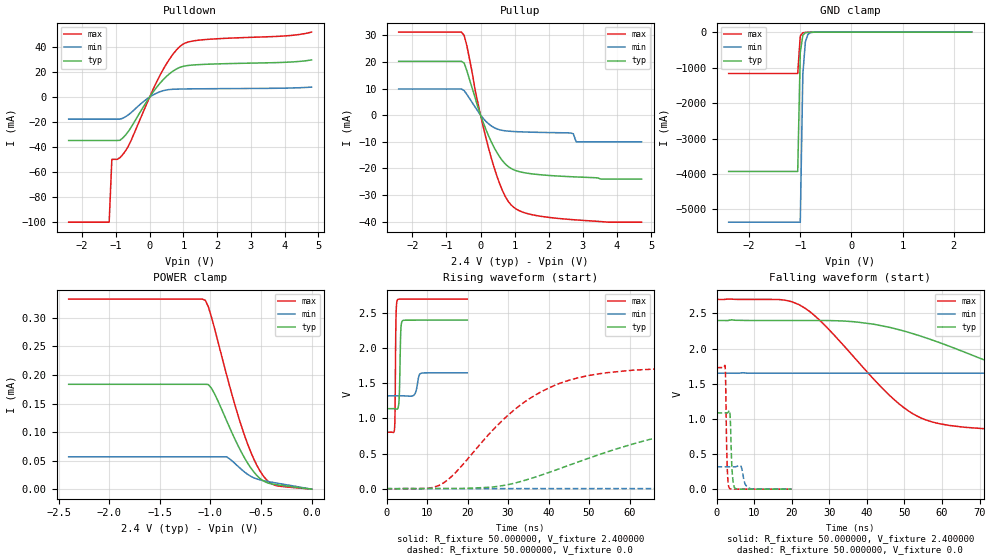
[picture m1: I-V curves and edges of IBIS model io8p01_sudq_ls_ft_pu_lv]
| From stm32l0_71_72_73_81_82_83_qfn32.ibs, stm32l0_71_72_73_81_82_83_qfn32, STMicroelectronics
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|   Model io8p01_sudq_ls_ft_pu_lv
[Model]  io8p01_sudq_ls_ft_pu_lv
Model_type I/O
Polarity   Non-Inverting
Enable   Active-Low
Vinl =   0.720000V
Vinh =   1.680000V
Vmeas =  1.200000V
Cref =   50.000000pF
Rref =   100.000000M
Vref =   0.0V
C_comp   2.317700pF   2.286600pF   2.332700pF
[Temperature Range]   25.000000   0.105000k   -40.000000
[Pullup Reference]   2.400000V   1.650000V   2.700000V
[Pulldown Reference]   0.0V   0.0V   0.0V
[POWER Clamp Reference]   2.400000V   1.650000V   2.700000V
[GND Clamp Reference]   0.0V   0.0V   0.0V
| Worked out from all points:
|   slope of the pulldown table from 0 to 0.36 V, typ, clamps not added: 28.4 ohm
|   slope of the pullup table from 0 to 0.36 V, typ, clamps not added: 32.2 ohm
|   GND clamp passes 1 mA (typ) near -0.65 V on its own axis
|   rising waveform, R_fixture 50.000000, V_fixture 2.400000: 20-80 % time 276ps typ, 630ps min, 183ps max; typ from 1.14 V to 2.4 V
|   rising waveform, R_fixture 50.000000, V_fixture 0.0: 20-80 % time 39.8ns typ, 107ns min, 19.4ns max; typ from 0.001 V to 1.09 V
|   falling waveform, R_fixture 50.000000, V_fixture 2.400000: 20-80 % time 41.3ns typ, 106ns min, 20.3ns max; typ from 2.4 V to 1.14 V
|   falling waveform, R_fixture 50.000000, V_fixture 0.0: 20-80 % time 457ps typ, 825ps min, 358ps max; typ from 1.09 V to 0.001 V
[Pulldown]
|Voltage   I(typ)   I(min)   I(max)
-2.4V     -34.71mA   -17.62mA   -100mA
-1.2V     -34.71mA   -17.62mA   -100mA
-1.12V    -34.71mA   -17.62mA   -49.77mA
-960mV    -34.71mA   -17.62mA   -49.77mA
-720mV    -30.52mA   -15.81mA   -43.24mA
-560mV    -24.66mA   -12.69mA   -35.31mA
-80mV     -3.3mA     -1.497mA   -4.982mA
320mV     11.47mA    4.39mA     18.08mA
640mV     19.72mA    6.139mA    32.34mA
960mV     24.33mA    6.432mA    41.77mA
1.52V     26.01mA    6.613mA    45.64mA
4.8V      29.64mA    7.944mA    51.92mA
[Pullup]
|Voltage   I(typ)   I(min)   I(max)
-2.4V     20.23mA    9.819mA    31.21mA
-560mV    20.23mA    9.819mA    31.21mA
-480mV    19.53mA    9.213mA    29.94mA
-400mV    16.65mA    7.776mA    25.99mA
0V        86fA       7.57pA     10fA
320mV     -10.16mA   -4.078mA   -16.34mA
640mV     -17.08mA   -5.718mA   -28.28mA
960mV     -20.45mA   -6.129mA   -34.49mA
2V        -22.64mA   -6.529mA   -38.4mA
2.72V     -23.16mA   -7mA       -39.27mA
2.8V      -23.2mA    -10mA      -39.35mA
4.72V     -24mA      -10mA      -40.2mA
[GND_clamp]
|Voltage   I(typ)   I(min)   I(max)
-2.4V     -3.929A    -5.359A    -1.166A
-1.05V    -3.929A    -5.359A    -1.166A
-1V       -574.5mA   -5.359A    -109.1mA
-950mV    -90.02mA   -1.192A    -18.55mA
-900mV    -18.41mA   -269.7mA   -9.049mA
-850mV    -6.764mA   -63.59mA   -6.579mA
-800mV    -4.027mA   -16.66mA   -4.859mA
-650mV    -1.043mA   -1.218mA   -1.146mA
2.35V     0A         0A         0A
[POWER_clamp]
|Voltage   I(typ)   I(min)   I(max)
-2.4V     183.7uA    56.67uA    333uA
-1.05V    183.7uA    56.67uA    330.8uA
-1.02V    183.2uA    56.67uA    319.3uA
-960mV    167.4uA    56.67uA    282.2uA
-840mV    120.1uA    56.67uA    200.3uA
-750mV    84.75uA    43.78uA    142.9uA
-690mV    63.55uA    34.11uA    108.5uA
-600mV    37.04uA    22.44uA    64.62uA
-510mV    18.73uA    16.34uA    31.91uA
-450mV    12.06uA    14.02uA    17.25uA
-360mV    8.154uA    11.11uA    6.782uA
0V        0A         0A         0A
[Ramp]
| variable   typ   min   max
dV/dt_r  0.65095/39.80921n   0.19020/0.10703u   1.03799/19.39127n
dV/dt_f  0.75624/41.29179n   0.19440/0.10610u   1.13751/20.24588n
R_load = 50.000000
[Rising Waveform]
R_fixture= 50.000000
V_fixture= 2.400000
V_fixture_min= 1.650000
V_fixture_max= 2.700000
|time   V(typ)   V(min)   V(max)
0s        1.14V      1.322V     804.2mV
1.962ns   1.14V      1.322V     842.5mV
2.122ns   1.138V     1.322V     1.188V
2.322ns   1.135V     1.322V     2.388V
2.683ns   1.134V     1.322V     2.687V
3.123ns   1.291V     1.323V     2.698V
3.524ns   2.247V     1.323V     2.699V
3.884ns   2.387V     1.323V     2.699V
8.569ns   2.4V       1.643V     2.7V
19.94ns   2.4V       1.65V      2.7V
[Rising Waveform]
R_fixture= 50.000000
V_fixture= 0.0
V_fixture_min= 0.0
V_fixture_max= 0.0
|time   V(typ)   V(min)   V(max)
0s        880.6uV    1.331mV    514.3uV
14.01ns   2.444mV    2.471mV    80.72mV
29.03ns   48.03mV    2.472mV    995mV
39.04ns   210.9mV    2.471mV    1.405V
48.05ns   396.2mV    2.479mV    1.589V
61.06ns   640.4mV    2.512mV    1.688V
85.09ns   917.7mV    3.566mV    1.725V
122.1ns   1.055V     40.2mV     1.73V
254.3ns   1.086V     268.1mV    1.73V
498.5ns   1.086V     318.6mV    1.73V
[Falling Waveform]
R_fixture= 50.000000
V_fixture= 2.400000
V_fixture_min= 1.650000
V_fixture_max= 2.700000
|time   V(typ)   V(min)   V(max)
0s        2.4V       1.65V      2.7V
22.02ns   2.4V       1.65V      2.624V
37.04ns   2.38V      1.65V      1.851V
52.05ns   2.216V     1.65V      1.079V
59.06ns   2.091V     1.65V      935.3mV
73.07ns   1.8V       1.65V      853.8mV
100.1ns   1.363V     1.65V      816mV
137.1ns   1.202V     1.636V     806mV
291.3ns   1.14V      1.38V      804.2mV
498.5ns   1.14V      1.322V     804.2mV
[Falling Waveform]
R_fixture= 50.000000
V_fixture= 0.0
V_fixture_min= 0.0
V_fixture_max= 0.0
|time   V(typ)   V(min)   V(max)
0s        1.086V     318.6mV    1.73V
2.282ns   1.086V     318.6mV    1.747V
2.402ns   1.086V     318.6mV    1.588V
2.843ns   1.085V     318.6mV    325.9mV
3.403ns   1.12V      318.6mV    16.81mV
3.644ns   1.017V     318.6mV    5.428mV
4.164ns   249.2mV    318.4mV    710.8uV
4.885ns   14.25mV    318.3mV    488.6uV
8.889ns   876.6uV    9.686mV    493.4uV
19.94ns   880.6uV    1.331mV    514.3uV
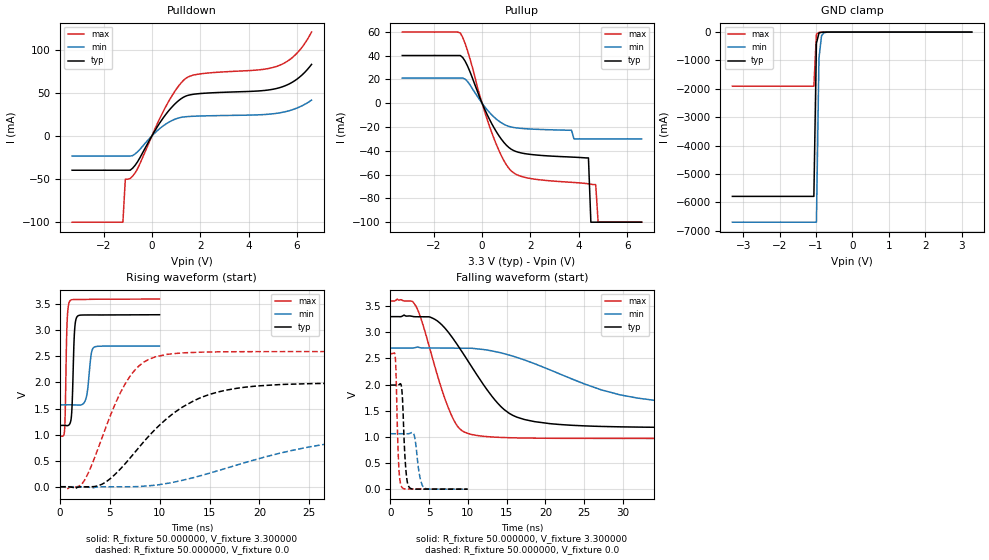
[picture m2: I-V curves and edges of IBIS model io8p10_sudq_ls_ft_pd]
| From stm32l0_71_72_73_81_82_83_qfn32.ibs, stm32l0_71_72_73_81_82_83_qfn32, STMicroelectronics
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|   Model io8p10_sudq_ls_ft_pd
[Model]  io8p10_sudq_ls_ft_pd
Model_type I/O
Polarity   Non-Inverting
Enable   Active-Low
Vinl =   0.990000V
Vinh =   2.310000V
Vmeas =  1.650000V
Cref =   50.000000pF
Rref =   100.000000M
Vref =   0.0V
C_comp   2.343000pF   2.309800pF   2.393900pF
[Temperature Range]   25.000000   0.125000k   -40.000000
[Pullup Reference]   3.300000V   2.700000V   3.600000V
[Pulldown Reference]   0.0V   0.0V   0.0V
[POWER Clamp Reference]   3.300000V   2.700000V   3.600000V
[GND Clamp Reference]   0.0V   0.0V   0.0V
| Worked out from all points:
|   slope of the pulldown table from 0 to 0.495 V, typ, clamps not added: 22.6 ohm
|   slope of the pullup table from 0 to 0.495 V, typ, clamps not added: 23.9 ohm
|   GND clamp passes 1 mA (typ) near -0.64 V on its own axis
|   rising waveform, R_fixture 50.000000, V_fixture 3.300000: 20-80 % time 207ps typ, 360ps min, 165ps max; typ from 1.18 V to 3.3 V
|   rising waveform, R_fixture 50.000000, V_fixture 0.0: 20-80 % time 6.56ns typ, 13.6ns min, 3.47ns max; typ from 0 V to 1.99 V
|   falling waveform, R_fixture 50.000000, V_fixture 3.300000: 20-80 % time 6.01ns typ, 12.6ns min, 3.3ns max; typ from 3.3 V to 1.18 V
|   falling waveform, R_fixture 50.000000, V_fixture 0.0: 20-80 % time 379ps typ, 552ps min, 301ps max; typ from 1.99 V to 0 V
[Pulldown]
|Voltage   I(typ)   I(min)   I(max)
-3.3V     -39.8mA    -23.38mA   -100mA
-1.2V     -39.8mA    -23.38mA   -100mA
-1.1V     -39.8mA    -23.38mA   -50.11mA
-900mV    -39.8mA    -23.38mA   -49.43mA
-700mV    -34.25mA   -21mA      -43.13mA
600mV     25.84mA    14.18mA    35.34mA
1V        38.32mA    19.82mA    53.81mA
1.4V      46.09mA    22.19mA    66.63mA
2V        49.05mA    23.02mA    71.83mA
5.2V      55.23mA    26.32mA    80.92mA
6V        65.76mA    32.26mA    95.84mA
6.6V      82.81mA    41.44mA    120.2mA
[Pullup]
|Voltage   I(typ)   I(min)   I(max)
-3.3V     40.02mA    21.08mA    59.7mA
-900mV    40.02mA    21.08mA    58.93mA
-600mV    31.19mA    18.17mA    44.04mA
500mV     -20.88mA   -11.78mA   -30.07mA
1.3V      -39.75mA   -20.41mA   -58.47mA
3.7V      -45.29mA   -22.8mA    -66.51mA
3.8V      -45.39mA   -30mA      -66.64mA
4.4V      -46mA      -30mA      -67.77mA
4.5V      -100mA     -30mA      -68.06mA
4.7V      -100mA     -30mA      -68.41mA
4.8V      -100mA     -30mA      -100mA
6.6V      -100mA     -30mA      -100mA
[GND_clamp]
|Voltage   I(typ)   I(min)   I(max)
-3.3V     -5.787A    -6.696A    -1.906A
-1.06V    -5.787A    -6.696A    -1.906A
-990mV    -393.4mA   -6.696A    -70.76mA
-920mV    -33.04mA   -919.4mA   -10.91mA
-850mV    -6.842mA   -131.3mA   -6.529mA
-780mV    -3.49mA    -21.08mA   -4.216mA
3.28V     73.94uA    88.61uA    51.47uA
[POWER_clamp]
|Voltage   I(typ)   I(min)   I(max)
-3.28V    0A         0A         0A
0V        0A         0A         0A
[Ramp]
| variable   typ   min   max
dV/dt_r  1.19406/6.55112n   0.62820/13.60552n   1.55520/3.47051n
dV/dt_f  1.27332/5.99980n   0.65328/12.52154n   1.57766/3.29329n
R_load = 50.000000
[Rising Waveform]
R_fixture= 50.000000
V_fixture= 3.300000
V_fixture_min= 2.700000
V_fixture_max= 3.600000
|time   V(typ)   V(min)   V(max)
0s        1.176V     1.571V     969.9mV
440.4ps   1.175V     1.571V     1.076V
700.7ps   1.172V     1.571V     3.169V
981ps     1.212V     1.571V     3.565V
1.181ns   1.496V     1.571V     3.587V
1.441ns   2.977V     1.569V     3.591V
1.722ns   3.267V     1.566V     3.592V
2.603ns   3.294V     1.699V     3.592V
3.363ns   3.295V     2.67V      3.595V
9.97ns    3.299V     2.698V     3.599V
[Rising Waveform]
R_fixture= 50.000000
V_fixture= 0.0
V_fixture_min= 0.0
V_fixture_max= 0.0
|time   V(typ)   V(min)   V(max)
0s        -126.7nV   -5.799uV   368.3uV
2.302ns   -2.081mV   -1.676mV   83.37mV
4.204ns   48.68mV    -878.1uV   940.8mV
6.507ns   437.8mV    -537.1uV   1.967V
7.908ns   754.3mV    3.22mV     2.317V
9.61ns    1.114V     30.17mV    2.494V
13.41ns   1.649V     176.8mV    2.576V
18.52ns   1.909V     461.1mV    2.59V
30.73ns   1.987V     918.5mV    2.592V
49.85ns   1.99V      1.06V      2.592V
[Falling Waveform]
R_fixture= 50.000000
V_fixture= 3.300000
V_fixture_min= 2.700000
V_fixture_max= 3.600000
|time   V(typ)   V(min)   V(max)
0s        3.299V     2.698V     3.599V
3.303ns   3.297V     2.709V     3.5V
5.506ns   3.266V     2.7V       2.471V
7.508ns   2.996V     2.697V     1.548V
8.709ns   2.747V     2.696V     1.196V
9.91ns    2.476V     2.695V     1.07V
14.21ns   1.587V     2.609V     989.4mV
17.32ns   1.331V     2.47V      977.7mV
29.63ns   1.192V     1.803V     970.3mV
49.85ns   1.176V     1.571V     969.9mV
[Falling Waveform]
R_fixture= 50.000000
V_fixture= 0.0
V_fixture_min= 0.0
V_fixture_max= 0.0
|time   V(typ)   V(min)   V(max)
0s        1.99V      1.06V      2.592V
660.7ps   1.99V      1.06V      2.503V
1.081ns   1.994V     1.06V      482.7mV
1.481ns   1.913V     1.06V      39.53mV
1.982ns   423.2mV    1.06V      3.541mV
2.442ns   36.98mV    1.064V     2.236mV
3.103ns   1.467mV    1.022V     2.325mV
3.764ns   667.8uV    274.8mV    2.476mV
4.244ns   683.2uV    41.26mV    2.271mV
9.97ns    -126.7nV   -5.799uV   368.3uV
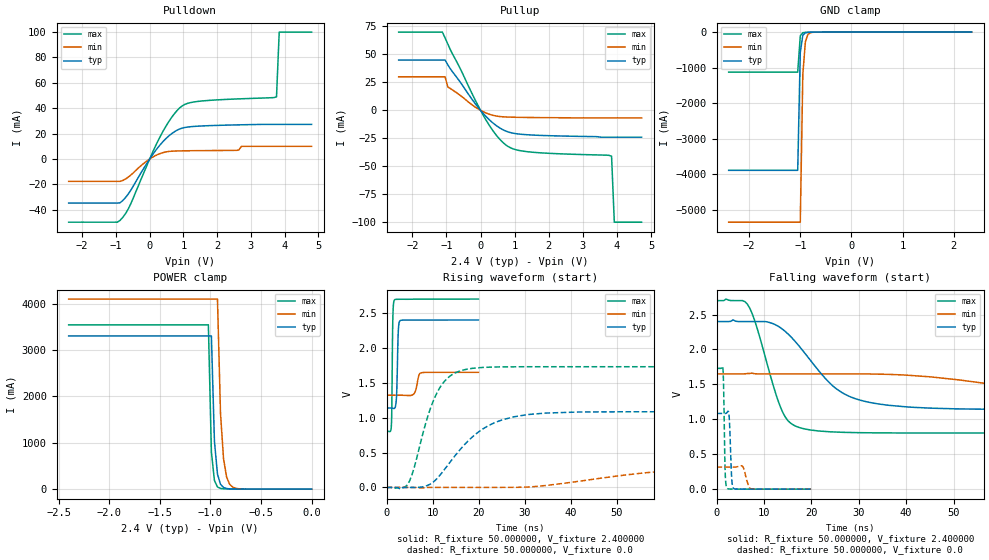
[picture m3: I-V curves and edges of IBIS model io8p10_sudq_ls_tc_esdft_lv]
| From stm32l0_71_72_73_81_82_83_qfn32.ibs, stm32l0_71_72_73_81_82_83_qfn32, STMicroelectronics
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|   Model io8p10_sudq_ls_tc_esdft_lv
[Model]  io8p10_sudq_ls_tc_esdft_lv
Model_type I/O
Polarity   Non-Inverting
Enable   Active-Low
Vinl =   0.720000V
Vinh =   1.680000V
Vmeas =  1.200000V
Cref =   50.000000pF
Rref =   100.000000M
Vref =   0.0V
C_comp   2.242700pF   2.201100pF   2.288600pF
[Temperature Range]   25.000000   0.105000k   -40.000000
[Pullup Reference]   2.400000V   1.650000V   2.700000V
[Pulldown Reference]   0.0V   0.0V   0.0V
[POWER Clamp Reference]   2.400000V   1.650000V   2.700000V
[GND Clamp Reference]   0.0V   0.0V   0.0V
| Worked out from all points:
|   slope of the pulldown table from 0 to 0.36 V, typ, clamps not added: 28.4 ohm
|   slope of the pullup table from 0 to 0.36 V, typ, clamps not added: 32.2 ohm
|   GND clamp passes 1 mA (typ) near -0.65 V on its own axis
|   POWER clamp passes 1 mA (typ) near -0.63 V on its own axis
|   rising waveform, R_fixture 50.000000, V_fixture 2.400000: 20-80 % time 279ps typ, 635ps min, 186ps max; typ from 1.14 V to 2.4 V
|   rising waveform, R_fixture 50.000000, V_fixture 0.0: 20-80 % time 9.54ns typ, 25.2ns min, 4.93ns max; typ from 0 V to 1.08 V
|   falling waveform, R_fixture 50.000000, V_fixture 2.400000: 20-80 % time 10.1ns typ, 27.2ns min, 4.96ns max; typ from 2.4 V to 1.14 V
|   falling waveform, R_fixture 50.000000, V_fixture 0.0: 20-80 % time 355ps typ, 761ps min, 262ps max; typ from 1.08 V to 0 V
[Pulldown]
|Voltage   I(typ)   I(min)   I(max)
-2.4V     -34.7mA    -17.62mA   -49.77mA
-880mV    -34.55mA   -17.62mA   -48.41mA
-560mV    -24.66mA   -12.69mA   -35.31mA
240mV     8.893mA    3.543mA    13.9mA
560mV     17.98mA    5.931mA    29.16mA
880mV     23.57mA    6.389mA    40.03mA
1.44V     25.89mA    6.593mA    45.41mA
2.64V     26.92mA    7mA        47.38mA
2.72V     26.96mA    10mA       47.46mA
3.76V     27.3mA     10mA       49mA
3.84V     27.3mA     10mA       100mA
4.8V      27.3mA     10mA       100mA
[Pullup]
|Voltage   I(typ)   I(min)   I(max)
-2.4V     45mA       30mA       70mA
-1.12V    45mA       30mA       70mA
-1.04V    45mA       30mA       64.8mA
-960mV    40.7mA     21mA       59.3mA
80mV      -2.838mA   -1.261mA   -4.478mA
480mV     -14.04mA   -5.167mA   -22.91mA
800mV     -19.2mA    -5.978mA   -32.18mA
1.04V     -20.85mA   -6.184mA   -35.23mA
1.44V     -21.93mA   -6.373mA   -37.19mA
3.84V     -24mA      -6.7mA     -41mA
3.92V     -24mA      -6.7mA     -100mA
4.72V     -24mA      -6.7mA     -100mA
[GND_clamp]
|Voltage   I(typ)   I(min)   I(max)
-2.4V     -3.892A    -5.353A    -1.127A
-1.05V    -3.892A    -5.353A    -1.127A
-1V       -568.8mA   -5.353A    -105.4mA
-950mV    -88.95mA   -1.19A     -18.03mA
-900mV    -18.15mA   -269.2mA   -8.959mA
-850mV    -6.699mA   -63.45mA   -6.568mA
-800mV    -4.014mA   -16.61mA   -4.858mA
-650mV    -1.043mA   -1.218mA   -1.146mA
2.35V     0A         0A         0A
[POWER_clamp]
|Voltage   I(typ)   I(min)   I(max)
-2.4V     3.303A     4.097A     3.542A
-1.02V    3.303A     4.097A     3.542A
-990mV    3.303A     4.097A     802.4mA
-960mV    1.032A     4.097A     186.5mA
-930mV    325.2mA    4.097A     47.59mA
-900mV    104.8mA    1.637A     15.78mA
-870mV    35.83mA    655.7mA    8.015mA
-840mV    13.93mA    263.9mA    5.668mA
-810mV    6.712mA    107.2mA    4.56mA
-780mV    4.088mA    44.39mA    3.763mA
-690mV    1.741mA    4.361mA    1.91mA
0V        0A         0A         0A
[Ramp]
| variable   typ   min   max
dV/dt_r  0.65070/9.52817n   0.18997/25.20237n   1.03800/4.90755n
dV/dt_f  0.75696/10.12210n   0.19686/27.14500n   1.13786/4.94934n
R_load = 50.000000
[Rising Waveform]
R_fixture= 50.000000
V_fixture= 2.400000
V_fixture_min= 1.650000
V_fixture_max= 2.700000
|time   V(typ)   V(min)   V(max)
0s        1.138V     1.322V     803.6mV
1.041ns   1.138V     1.322V     875.2mV
1.161ns   1.137V     1.322V     1.218V
1.361ns   1.134V     1.322V     2.399V
1.722ns   1.134V     1.322V     2.687V
2.122ns   1.255V     1.322V     2.696V
2.563ns   2.251V     1.322V     2.697V
2.923ns   2.389V     1.322V     2.697V
7.568ns   2.399V     1.643V     2.699V
19.94ns   2.4V       1.65V      2.7V
[Rising Waveform]
R_fixture= 50.000000
V_fixture= 0.0
V_fixture_min= 0.0
V_fixture_max= 0.0
|time   V(typ)   V(min)   V(max)
0s        -407.2nV   -2.921uV   -28.5nV
5.005ns   -684.8uV   102.8uV    92.86mV
9.51ns    47.94mV    -157.3uV   1.13V
12.01ns   209.8mV    -151.2uV   1.474V
15.02ns   466.6mV    -154.7uV   1.645V
19.02ns   746.2mV    -142.9uV   1.71V
27.53ns   1.011V     1.384mV    1.729V
41.54ns   1.081V     86.56mV    1.73V
90.09ns   1.085V     308.1mV    1.73V
249.2ns   1.085V     316.6mV    1.73V
[Falling Waveform]
R_fixture= 50.000000
V_fixture= 2.400000
V_fixture_min= 1.650000
V_fixture_max= 2.700000
|time   V(typ)   V(min)   V(max)
0s        2.4V       1.65V      2.7V
6.507ns   2.4V       1.656V     2.649V
8.008ns   2.4V       1.653V     2.423V
12.51ns   2.351V     1.65V      1.364V
14.51ns   2.258V     1.65V      1.032V
21.52ns   1.699V     1.65V      833.4mV
29.03ns   1.302V     1.65V      810.4mV
45.05ns   1.16V      1.609V     804mV
96.6ns    1.139V     1.343V     803.6mV
249.2ns   1.138V     1.322V     803.6mV
[Falling Waveform]
R_fixture= 50.000000
V_fixture= 0.0
V_fixture_min= 0.0
V_fixture_max= 0.0
|time   V(typ)   V(min)   V(max)
0s        1.085V     316.6mV    1.73V
1.361ns   1.085V     316.6mV    1.719V
1.522ns   1.084V     316.6mV    1.37V
1.802ns   1.084V     316.6mV    288.1mV
2.202ns   1.097V     316.6mV    15.48mV
2.643ns   1.054V     316.6mV    2.308mV
3.203ns   152.1mV    316.4mV    1.604mV
3.644ns   8.819mV    316.1mV    1.484mV
7.287ns   381.8uV    5.853mV    1.171mV
19.94ns   -407.2nV   -2.921uV   -28.5nV
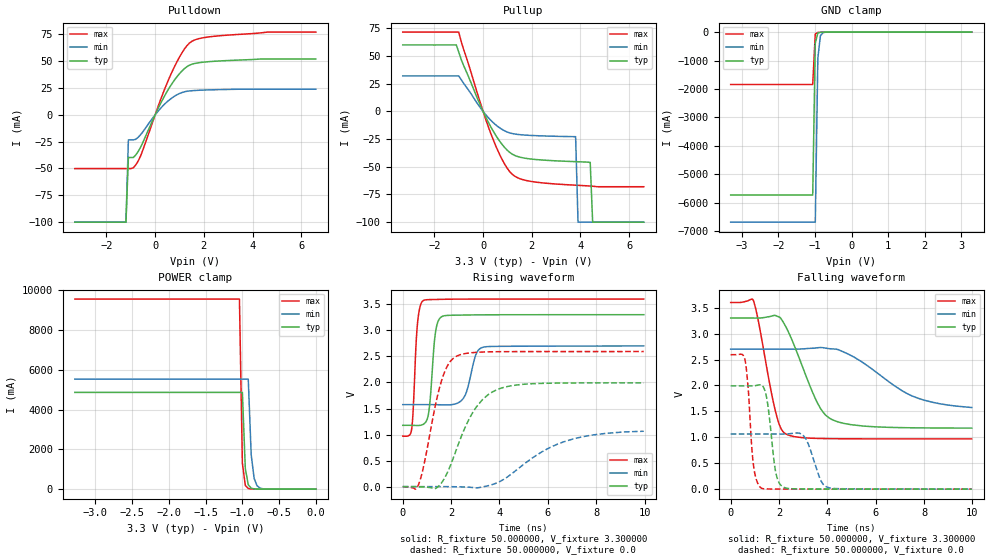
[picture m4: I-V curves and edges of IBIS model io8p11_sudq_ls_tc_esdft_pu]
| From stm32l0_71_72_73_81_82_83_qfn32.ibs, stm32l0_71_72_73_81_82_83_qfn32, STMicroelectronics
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|   Model io8p11_sudq_ls_tc_esdft_pu
[Model]  io8p11_sudq_ls_tc_esdft_pu
Model_type I/O
Polarity   Non-Inverting
Enable   Active-Low
Vinl =   0.990000V
Vinh =   2.310000V
Vmeas =  1.650000V
Cref =   50.000000pF
Rref =   100.000000M
Vref =   0.0V
C_comp   2.248300pF   2.207300pF   2.311900pF
[Temperature Range]   25.000000   0.125000k   -40.000000
[Pullup Reference]   3.300000V   2.700000V   3.600000V
[Pulldown Reference]   0.0V   0.0V   0.0V
[POWER Clamp Reference]   3.300000V   2.700000V   3.600000V
[GND Clamp Reference]   0.0V   0.0V   0.0V
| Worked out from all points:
|   slope of the pulldown table from 0 to 0.495 V, typ, clamps not added: 22.6 ohm
|   slope of the pullup table from 0 to 0.495 V, typ, clamps not added: 23.9 ohm
|   GND clamp passes 1 mA (typ) near -0.64 V on its own axis
|   POWER clamp passes 1 mA (typ) near -0.63 V on its own axis
|   rising waveform, R_fixture 50.000000, V_fixture 3.300000: 20-80 % time 210ps typ, 363ps min, 165ps max; typ from 1.18 V to 3.3 V
|   rising waveform, R_fixture 50.000000, V_fixture 0.0: 20-80 % time 1.19ns typ, 2.19ns min, 713ps max; typ from 0.001 V to 1.99 V
|   falling waveform, R_fixture 50.000000, V_fixture 3.300000: 20-80 % time 1.12ns typ, 2.14ns min, 643ps max; typ from 3.3 V to 1.18 V
|   falling waveform, R_fixture 50.000000, V_fixture 0.0: 20-80 % time 291ps typ, 460ps min, 230ps max; typ from 1.99 V to 0.001 V
[Pulldown]
|Voltage   I(typ)   I(min)   I(max)
-3.3V     -100mA     -100mA     -50.11mA
-1.2V     -100mA     -100mA     -50.11mA
-1.1V     -39.8mA    -23.37mA   -50.11mA
-900mV    -39.8mA    -23.37mA   -49.43mA
-600mV    -30.26mA   -18.59mA   -38.38mA
500mV     22.11mA    12.28mA    30.06mA
900mV     35.58mA    18.71mA    49.62mA
1.3V      44.74mA    21.88mA    64.23mA
1.7V      48.13mA    22.72mA    70.3mA
2.4V      49.79mA    23.31mA    73.03mA
4.6V      51.9mA     23.82mA    77mA
6.6V      51.9mA     23.82mA    77mA
[Pullup]
|Voltage   I(typ)   I(min)   I(max)
-3.3V     60mA       32mA       71.6mA
-1.1V     60mA       32mA       71.6mA
-1V       53.5mA     32mA       71.6mA
-100mV    4.893mA    2.926mA    6.861mA
400mV     -17.21mA   -9.813mA   -24.69mA
900mV     -32.92mA   -17.72mA   -48.15mA
1.3V      -39.75mA   -20.41mA   -58.47mA
3.8V      -45.36mA   -22.8mA    -66.6mA
3.9V      -45.44mA   -100mA     -66.72mA
4.4V      -46mA      -100mA     -67.4mA
4.5V      -100mA     -100mA     -67.56mA
6.6V      -100mA     -100mA     -68mA
[GND_clamp]
|Voltage   I(typ)   I(min)   I(max)
-3.3V     -5.732A    -6.688A    -1.842A
-1.06V    -5.732A    -6.688A    -1.842A
-990mV    -389.4mA   -6.688A    -68.34mA
-920mV    -32.57mA   -918.2mA   -10.72mA
-850mV    -6.763mA   -131mA     -6.509mA
-780mV    -3.471mA   -21mA      -4.208mA
3.28V     0A         0A         0A
[POWER_clamp]
|Voltage   I(typ)   I(min)   I(max)
-3.28V    4.87A      5.538A     9.569A
-1.04V    4.87A      5.538A     9.569A
-1V       4.87A      5.538A     1.315A
-960mV    1.032A     5.538A     186.5mA
-920mV    222.2mA    5.538A     31.65mA
-880mV    50.75mA    1.734A     9.59mA
-840mV    13.94mA    544.9mA    5.676mA
-800mV    5.568mA    172.7mA    4.284mA
-760mV    3.243mA    55.85mA    3.306mA
-680mV    1.609mA    7mA        1.749mA
0V        0A         0A         0A
[Ramp]
| variable   typ   min   max
dV/dt_r  1.19461/1.19250n   0.60784/2.06422n   1.55540/0.71136n
dV/dt_f  1.27146/1.12105n   0.59196/1.93007n   1.57743/0.64180n
R_load = 50.000000
[Rising Waveform]
R_fixture= 50.000000
V_fixture= 3.300000
V_fixture_min= 2.700000
V_fixture_max= 3.600000
|time   V(typ)   V(min)   V(max)
0s        1.178V     1.575V     970mV
360.4ps   1.177V     1.575V     1.082V
600.6ps   1.175V     1.575V     3.082V
860.9ps   1.2V       1.575V     3.574V
1.081ns   1.444V     1.575V     3.589V
1.381ns   3.036V     1.573V     3.592V
1.642ns   3.27V      1.571V     3.595V
2.523ns   3.293V     1.707V     3.599V
3.283ns   3.297V     2.67V      3.6V
9.97ns    3.3V       2.7V       3.6V
[Rising Waveform]
R_fixture= 50.000000
V_fixture= 0.0
V_fixture_min= 0.0
V_fixture_max= 0.0
|time   V(typ)   V(min)   V(max)
0s        1.074mV    1.84mV     537.2uV
640.6ps   138.3uV    1.821mV    27.26mV
860.9ps   -4.815mV   1.837mV    386mV
1.562ns   50.67mV    2.006mV    1.965V
1.862ns   288.2mV    1.464mV    2.33V
2.182ns   665.8mV    -821.6uV   2.493V
3.043ns   1.528V     -22.23mV   2.578V
4.024ns   1.883V     101.4mV    2.591V
6.627ns   1.989V     856.1mV    2.593V
9.97ns    1.993V     1.064V     2.593V
[Falling Waveform]
R_fixture= 50.000000
V_fixture= 3.300000
V_fixture_min= 2.700000
V_fixture_max= 3.600000
|time   V(typ)   V(min)   V(max)
0s        3.3V       2.7V       3.6V
940.9ps   3.3V       2.7V       3.636V
1.862ns   3.348V     2.7V       1.487V
2.062ns   3.3V       2.7V       1.188V
2.302ns   3.114V     2.7V       1.061V
3.604ns   1.65V      2.728V     979.1mV
4.224ns   1.335V     2.704V     973.7mV
5.105ns   1.237V     2.546V     971.2mV
7.508ns   1.184V     1.798V     970.1mV
9.97ns    1.178V     1.575V     970mV
[Falling Waveform]
R_fixture= 50.000000
V_fixture= 0.0
V_fixture_min= 0.0
V_fixture_max= 0.0
|time   V(typ)   V(min)   V(max)
0s        1.993V     1.064V     2.593V
600.6ps   1.992V     1.064V     2.476V
940.9ps   1.994V     1.064V     473mV
1.261ns   2.01V      1.064V     22.99mV
1.502ns   1.729V     1.064V     4.744mV
1.882ns   289.1mV    1.064V     3.143mV
2.182ns   40.24mV    1.064V     2.559mV
3.043ns   4.209mV    1.014V     1.425mV
4.084ns   2.536mV    25.22mV    807.3uV
9.97ns    1.074mV    1.84mV     537.2uV
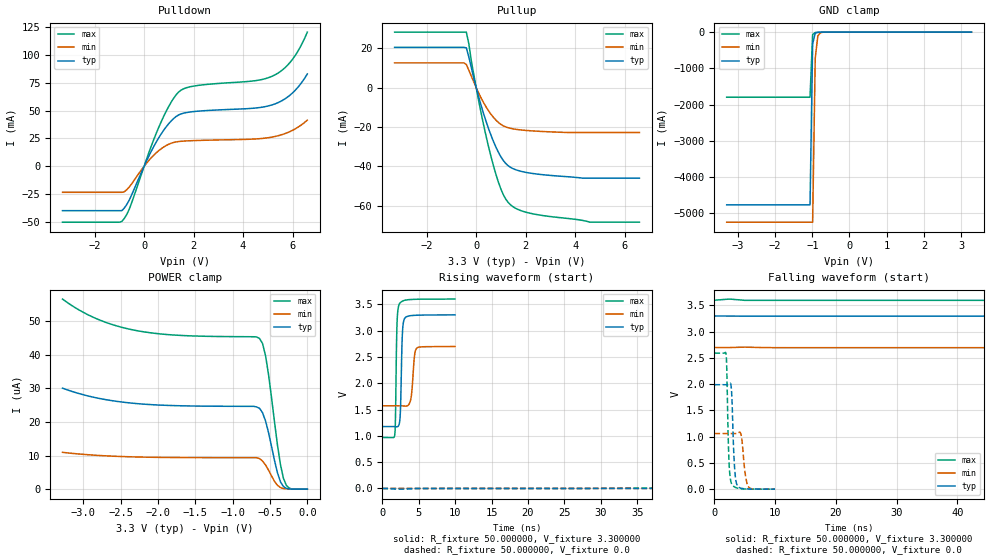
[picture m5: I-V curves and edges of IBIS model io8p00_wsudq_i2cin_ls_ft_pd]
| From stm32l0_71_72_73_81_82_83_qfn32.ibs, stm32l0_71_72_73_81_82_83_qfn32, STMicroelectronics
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|   Model io8p00_wsudq_i2cin_ls_ft_pd
[Model]  io8p00_wsudq_i2cin_ls_ft_pd
Model_type I/O
Polarity   Non-Inverting
Enable   Active-Low
Vinl =   0.990000V
Vinh =   2.310000V
Vmeas =  1.650000V
Cref =   50.000000pF
Rref =   100.000000M
Vref =   0.0V
C_comp   3.020400pF   2.988200pF   3.054500pF
[Temperature Range]   25.000000   0.125000k   -40.000000
[Pullup Reference]   3.300000V   2.700000V   3.600000V
[Pulldown Reference]   0.0V   0.0V   0.0V
[POWER Clamp Reference]   3.300000V   2.700000V   3.600000V
[GND Clamp Reference]   0.0V   0.0V   0.0V
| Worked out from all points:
|   slope of the pulldown table from 0 to 0.495 V, typ, clamps not added: 22.6 ohm
|   slope of the pullup table from 0 to 0.495 V, typ, clamps not added: 23.9 ohm
|   GND clamp passes 1 mA (typ) near -0.64 V on its own axis
|   rising waveform, R_fixture 50.000000, V_fixture 3.300000: 20-80 % time 222ps typ, 369ps min, 182ps max; typ from 1.18 V to 3.3 V
|   rising waveform, R_fixture 50.000000, V_fixture 0.0: 20-80 % time 204ns typ, 426ns min, 99.3ns max; typ from 0 V to 1.99 V
|   falling waveform, R_fixture 50.000000, V_fixture 3.300000: 20-80 % time 192ns typ, 382ns min, 105ns max; typ from 3.3 V to 1.18 V
|   falling waveform, R_fixture 50.000000, V_fixture 0.0: 20-80 % time 405ps typ, 572ps min, 327ps max; typ from 1.99 V to 0 V
[Pulldown]
|Voltage   I(typ)   I(min)   I(max)
-3.3V     -39.83mA   -23.37mA   -50.2mA
-900mV    -39.83mA   -23.37mA   -49.53mA
-600mV    -30.28mA   -18.59mA   -38.45mA
500mV     22.11mA    12.28mA    30.1mA
1V        38.33mA    19.81mA    53.88mA
1.4V      46.1mA     22.18mA    66.72mA
2V        49.07mA    23.02mA    71.93mA
4.4V      52.05mA    24.38mA    76.53mA
5.2V      55.25mA    26.3mA     81.02mA
5.6V      59.18mA    28.57mA    86.57mA
6V        65.79mA    32.24mA    95.97mA
6.6V      82.83mA    41.41mA    120.4mA
[Pullup]
|Voltage   I(typ)   I(min)   I(max)
-3.3V     20.5mA     12.63mA    28.27mA
-400mV    20.25mA    11.77mA    28.27mA
-300mV    15.65mA    8.931mA    22.44mA
-200mV    10.4mA     5.946mA    13.84mA
100mV     -4.685mA   -2.744mA   -6.647mA
600mV     -24.29mA   -13.56mA   -35.12mA
1V        -35.2mA    -18.69mA   -51.62mA
1.2V      -38.62mA   -19.99mA   -56.79mA
1.4V      -40.6mA    -20.72mA   -59.71mA
2.2V      -43.48mA   -21.92mA   -63.91mA
4.6V      -46.01mA   -22.8mA    -68.41mA
6.6V      -46.01mA   -22.8mA    -68.41mA
[GND_clamp]
|Voltage   I(typ)   I(min)   I(max)
-3.3V     -4.766A    -5.244A    -1.797A
-1.06V    -4.766A    -5.244A    -1.797A
-990mV    -326.6mA   -5.244A    -67.91mA
-920mV    -28.93mA   -722.1mA   -10.97mA
-850mV    -6.625mA   -104.2mA   -6.541mA
-780mV    -3.477mA   -17.29mA   -4.218mA
-500mV    -68.5uA    -183uA     -41.48uA
3.28V     73.94uA    88.61uA    51.47uA
[POWER_clamp]
|Voltage   I(typ)   I(min)   I(max)
-3.28V    30.07uA    10.97uA    56.59uA
-2.84V    27.25uA    10.1uA     50.89uA
-2.32V    25.55uA    9.602uA    47.34uA
-640mV    24.06uA    9.099uA    44.84uA
-600mV    22.76uA    8.364uA    43.37uA
-560mV    20.32uA    7.211uA    39.74uA
-520mV    16.86uA    5.675uA    34.14uA
-400mV    4.841uA    1.145uA    13.1uA
-360mV    2.184uA    477.2nA    7.288uA
-320mV    772.4nA    180.3nA    3.213uA
-240mV    60.03nA    0A         295.3nA
0V        0A         0A         0A
[Ramp]
| variable   typ   min   max
dV/dt_r  1.19400/0.20353u   0.61206/0.42683u   1.55520/99.14625n
dV/dt_f  1.27272/0.19144u   0.63720/0.38170u   1.57834/0.10504u
R_load = 50.000000
[Rising Waveform]
R_fixture= 50.000000
V_fixture= 3.300000
V_fixture_min= 2.700000
V_fixture_max= 3.600000
|time   V(typ)   V(min)   V(max)
0s        1.176V     1.571V     968.8mV
1.702ns   1.176V     1.571V     1.015V
2.022ns   1.172V     1.571V     3.154V
2.342ns   1.243V     1.571V     3.507V
2.503ns   1.569V     1.571V     3.535V
2.743ns   2.913V     1.57V      3.558V
3.023ns   3.222V     1.567V     3.575V
3.884ns   3.284V     1.684V     3.591V
4.745ns   3.292V     2.669V     3.596V
9.97ns    3.299V     2.698V     3.599V
[Rising Waveform]
R_fixture= 50.000000
V_fixture= 0.0
V_fixture_min= 0.0
V_fixture_max= 0.0
|time   V(typ)   V(min)   V(max)
0s        2.467nV    17.45nV    5.594nV
47.55ns   347.3uV    -21.65uV   62.19mV
100.1ns   75.22mV    12.42uV    913.1mV
165.2ns   455.6mV    6.638mV    1.936V
207.7ns   765.9mV    17.07mV    2.308V
255.3ns   1.09V      54.38mV    2.485V
370.4ns   1.626V     209.4mV    2.576V
503ns     1.879V     441.4mV    2.59V
865.9ns   1.986V     907.2mV    2.592V
1.246us   1.99V      1.06V      2.592V
[Falling Waveform]
R_fixture= 50.000000
V_fixture= 3.300000
V_fixture_min= 2.700000
V_fixture_max= 3.600000
|time   V(typ)   V(min)   V(max)
0s        3.299V     2.698V     3.599V
82.58ns   3.296V     2.695V     3.489V
150.2ns   3.187V     2.695V     2.486V
212.7ns   2.834V     2.692V     1.576V
247.7ns   2.593V     2.682V     1.235V
285.3ns   2.323V     2.66V      1.082V
390.4ns   1.637V     2.548V     997.6mV
488ns     1.343V     2.387V     979.3mV
835.8ns   1.194V     1.776V     969.3mV
1.246us   1.176V     1.571V     968.8mV
[Falling Waveform]
R_fixture= 50.000000
V_fixture= 0.0
V_fixture_min= 0.0
V_fixture_max= 0.0
|time   V(typ)   V(min)   V(max)
0s        1.99V      1.06V      2.592V
1.922ns   1.99V      1.06V      2.565V
2.022ns   1.99V      1.06V      2.324V
2.402ns   1.996V     1.06V      512mV
2.823ns   1.855V     1.06V      104mV
3.243ns   554.9mV    1.06V      47.8mV
3.704ns   86.71mV    1.062V     22.3mV
4.404ns   17.79mV    1.027V     6.946mV
5.546ns   3.817mV    53.46mV    2.84mV
9.97ns    2.467nV    17.45nV    5.594nV
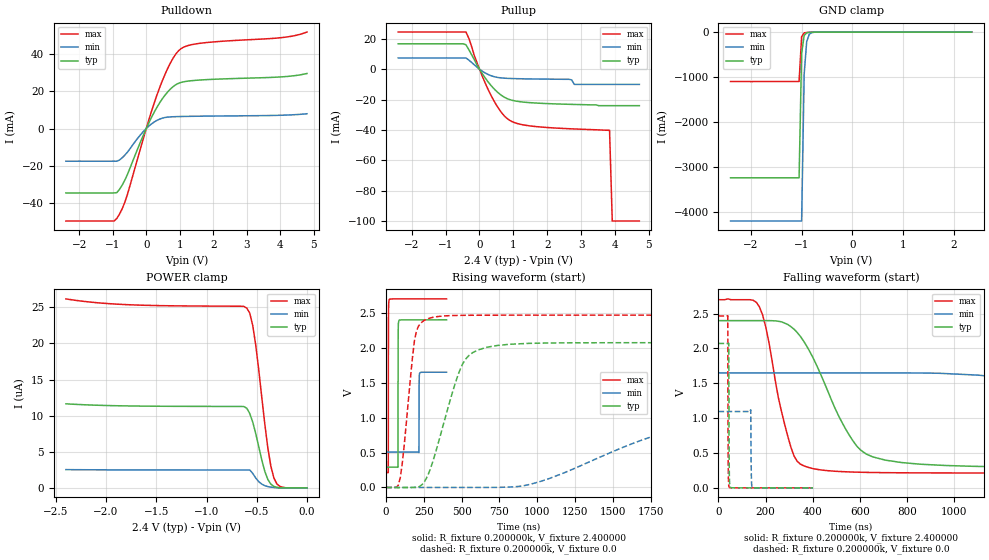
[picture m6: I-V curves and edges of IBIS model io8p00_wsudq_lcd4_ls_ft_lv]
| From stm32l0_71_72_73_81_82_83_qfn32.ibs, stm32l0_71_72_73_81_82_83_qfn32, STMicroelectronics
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|   Model io8p00_wsudq_lcd4_ls_ft_lv
[Model]  io8p00_wsudq_lcd4_ls_ft_lv
Model_type I/O
Polarity   Non-Inverting
Enable   Active-Low
Vinl =   0.720000V
Vinh =   1.680000V
Vmeas =  1.200000V
Cref =   50.000000pF
Rref =   100.000000M
Vref =   0.0V
C_comp   3.178800pF   3.170000pF   3.206700pF
[Temperature Range]   25.000000   0.105000k   -40.000000
[Pullup Reference]   2.400000V   1.650000V   2.700000V
[Pulldown Reference]   0.0V   0.0V   0.0V
[POWER Clamp Reference]   2.400000V   1.650000V   2.700000V
[GND Clamp Reference]   0.0V   0.0V   0.0V
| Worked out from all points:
|   slope of the pulldown table from 0 to 0.36 V, typ, clamps not added: 28.5 ohm
|   slope of the pullup table from 0 to 0.36 V, typ, clamps not added: 32.2 ohm
|   GND clamp passes 1 mA (typ) near -0.64 V on its own axis
|   rising waveform, R_fixture 0.200000k, V_fixture 2.400000: 20-80 % time 734ps typ, 886ps min, 838ps max; typ from 0.291 V to 2.4 V
|   rising waveform, R_fixture 0.200000k, V_fixture 0.0: 20-80 % time 169ns typ, 818ns min, 66.3ns max; typ from 0 V to 2.07 V
|   falling waveform, R_fixture 0.200000k, V_fixture 2.400000: 20-80 % time 179ns typ, 725ns min, 89.4ns max; typ from 2.4 V to 0.291 V
|   falling waveform, R_fixture 0.200000k, V_fixture 0.0: 20-80 % time 1.27ns typ, 1.81ns min, 1.09ns max; typ from 2.07 V to 0 V
[Pulldown]
|Voltage   I(typ)   I(min)   I(max)
-2.4V     -34.7mA    -17.61mA   -49.82mA
-960mV    -34.7mA    -17.61mA   -49.82mA
-880mV    -34.55mA   -17.61mA   -48.46mA
-720mV    -30.52mA   -15.79mA   -43.28mA
-560mV    -24.65mA   -12.68mA   -35.33mA
0V        326fA      0A         20fA
400mV     13.84mA    5.066mA    22.03mA
720mV     21.24mA    6.254mA    35.26mA
1.04V     24.82mA    6.464mA    43.03mA
1.6V      26.11mA    6.627mA    45.88mA
4V        27.76mA    7.125mA    48.87mA
4.8V      29.64mA    7.94mA     51.96mA
[Pullup]
|Voltage   I(typ)   I(min)   I(max)
-2.4V     16.77mA    7.419mA    24.51mA
-400mV    16.1mA     7.419mA    24.51mA
0V        80fA       7.57pA     0A
320mV     -10.16mA   -4.078mA   -16.34mA
640mV     -17.08mA   -5.718mA   -28.28mA
960mV     -20.45mA   -6.128mA   -34.49mA
1.76V     -22.39mA   -6.47mA    -37.97mA
2.64V     -23.11mA   -6.64mA    -39.19mA
2.8V      -23.2mA    -10mA      -39.35mA
3.84V     -24mA      -10mA      -40.2mA
3.92V     -24mA      -10mA      -100mA
4.72V     -24mA      -10mA      -100mA
[GND_clamp]
|Voltage   I(typ)   I(min)   I(max)
-2.4V     -3.238A    -4.199A    -1.101A
-1.05V    -3.238A    -4.199A    -1.101A
-1V       -476.5mA   -4.199A    -104.7mA
-950mV    -76.68mA   -936.1mA   -18.74mA
-900mV    -16.85mA   -213.2mA   -9.358mA
-850mV    -6.706mA   -51.12mA   -6.778mA
-800mV    -4.108mA   -13.92mA   -4.995mA
-650mV    -1.07mA    -1.211mA   -1.175mA
2.35V     0A         0A         0A
[POWER_clamp]
|Voltage   I(typ)   I(min)   I(max)
-2.4V     11.64uA    2.527uA    26.18uA
-1.86V    11.37uA    2.49uA     25.43uA
-600mV    11.04uA    2.475uA    24.9uA
-570mV    10.3uA     2.473uA    24.21uA
-540mV    9.097uA    2.001uA    22.48uA
-510mV    7.497uA    1.351uA    19.73uA
-450mV    3.846uA    513.2nA    12.52uA
-390mV    1.155uA    176.1nA    5.528uA
-360mV    508.6nA    103.4nA    2.997uA
-330mV    204.7nA    61.05nA    1.375uA
-270mV    0A         0A         195.3nA
0V        0A         0A         0A
[Ramp]
| variable   typ   min   max
dV/dt_r  0.65070/0.30191u   0.18995/0.80832u   1.03800/0.14373u
dV/dt_f  0.75690/0.32114u   0.19674/0.84576u   1.13815/0.15954u
R_load = 50.000000
[Rising Waveform]
R_fixture= 0.200000k
V_fixture= 2.400000
V_fixture_min= 1.650000
V_fixture_max= 2.700000
|time   V(typ)   V(min)   V(max)
0s        290.7mV    507.1mV    212.9mV
14.01ns   290.7mV    507.1mV    219.8mV
15.22ns   290.7mV    507.1mV    2.337V
19.62ns   290.7mV    507.1mV    2.688V
77.68ns   289mV      507.1mV    2.7V
79.68ns   2.205V     507.1mV    2.7V
84.48ns   2.387V     507.1mV    2.7V
216.2ns   2.4V       502.4mV    2.7V
222.2ns   2.4V       1.639V     2.7V
400ns     2.4V       1.65V      2.7V
[Rising Waveform]
R_fixture= 0.200000k
V_fixture= 0.0
V_fixture_min= 0.0
V_fixture_max= 0.0
|time   V(typ)   V(min)   V(max)
0s        2.057nV    12.8nV     1.581nV
93.43ns   -110.6uV   12.8nV     141mV
200.2ns   1.334mV    12.8nV     2.238V
266.9ns   134.8mV    -23.34uV   2.407V
347ns     653mV      -23.38uV   2.449V
520.5ns   1.821V     20.03uV    2.465V
840.8ns   2.052V     9.215mV    2.467V
1.895us   2.072V     818mV      2.467V
2.776us   2.072V     1.06V      2.467V
13.33us   2.072V     1.095V     2.467V
[Falling Waveform]
R_fixture= 0.200000k
V_fixture= 2.400000
V_fixture_min= 1.650000
V_fixture_max= 2.700000
|time   V(typ)   V(min)   V(max)
0s        2.4V       1.65V      2.7V
160.2ns   2.4V       1.65V      2.663V
320.3ns   2.276V     1.65V      456.5mV
507.2ns   1.047V     1.65V      235.7mV
613.9ns   513.9mV    1.65V      222.8mV
787.5ns   359.6mV    1.649V     215.8mV
1.348us   297mV      1.497V     213mV
2.189us   290.9mV    725.2mV    212.9mV
2.95us    290.7mV    552.3mV    212.9mV
13.33us   290.7mV    507.1mV    212.9mV
[Falling Waveform]
R_fixture= 0.200000k
V_fixture= 0.0
V_fixture_min= 0.0
V_fixture_max= 0.0
|time   V(typ)   V(min)   V(max)
0s        2.072V     1.095V     2.467V
39.24ns   2.072V     1.095V     2.471V
41.24ns   2.072V     1.095V     311.1mV
43.64ns   2.071V     1.095V     29.39mV
45.25ns   445.4mV    1.095V     11.56mV
49.65ns   10.95mV    1.095V     2.231mV
136.5ns   27.94uV    1.12V      142.9uV
139.3ns   27.77uV    163mV      142.9uV
143.3ns   27.54uV    7.191mV    142.9uV
400ns     2.057nV    12.8nV     1.581nV
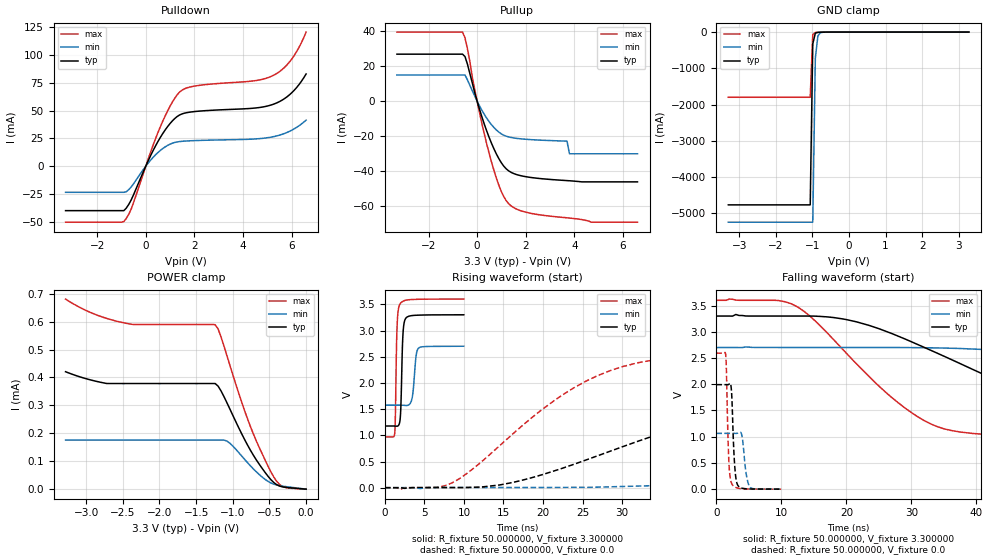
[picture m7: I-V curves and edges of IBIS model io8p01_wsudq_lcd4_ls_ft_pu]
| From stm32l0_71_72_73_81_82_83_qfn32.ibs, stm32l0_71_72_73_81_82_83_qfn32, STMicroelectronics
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|   Model io8p01_wsudq_lcd4_ls_ft_pu
[Model]  io8p01_wsudq_lcd4_ls_ft_pu
Model_type I/O
Polarity   Non-Inverting
Enable   Active-Low
Vinl =   0.990000V
Vinh =   2.310000V
Vmeas =  1.650000V
Cref =   50.000000pF
Rref =   100.000000M
Vref =   0.0V
C_comp   3.263700pF   3.224700pF   3.309000pF
[Temperature Range]   25.000000   0.125000k   -40.000000
[Pullup Reference]   3.300000V   2.700000V   3.600000V
[Pulldown Reference]   0.0V   0.0V   0.0V
[POWER Clamp Reference]   3.300000V   2.700000V   3.600000V
[GND Clamp Reference]   0.0V   0.0V   0.0V
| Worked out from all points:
|   slope of the pulldown table from 0 to 0.495 V, typ, clamps not added: 22.6 ohm
|   slope of the pullup table from 0 to 0.495 V, typ, clamps not added: 23.9 ohm
|   GND clamp passes 1 mA (typ) near -0.64 V on its own axis
|   rising waveform, R_fixture 50.000000, V_fixture 3.300000: 20-80 % time 236ps typ, 378ps min, 200ps max; typ from 1.18 V to 3.3 V
|   rising waveform, R_fixture 50.000000, V_fixture 0.0: 20-80 % time 27.1ns typ, 59.7ns min, 13.6ns max; typ from 0.001 V to 1.99 V
|   falling waveform, R_fixture 50.000000, V_fixture 3.300000: 20-80 % time 24.2ns typ, 53.2ns min, 13.3ns max; typ from 3.3 V to 1.18 V
|   falling waveform, R_fixture 50.000000, V_fixture 0.0: 20-80 % time 419ps typ, 579ps min, 343ps max; typ from 1.99 V to 0.001 V
[Pulldown]
|Voltage   I(typ)   I(min)   I(max)
-3.3V     -39.83mA   -23.37mA   -50.2mA
-900mV    -39.83mA   -23.37mA   -49.52mA
-600mV    -30.28mA   -18.59mA   -38.45mA
100mV     4.867mA    2.821mA    6.48mA
600mV     25.85mA    14.17mA    35.39mA
1V        38.33mA    19.81mA    53.88mA
1.4V      46.1mA     22.18mA    66.72mA
2V        49.07mA    23.02mA    71.93mA
4.4V      52.05mA    24.38mA    76.53mA
5.2V      55.25mA    26.31mA    81.02mA
6V        65.78mA    32.24mA    95.96mA
6.6V      82.83mA    41.41mA    120.4mA
[Pullup]
|Voltage   I(typ)   I(min)   I(max)
-3.3V     26.78mA    14.88mA    39.37mA
-600mV    26.78mA    14.88mA    39.37mA
-400mV    21.16mA    12.2mA     30.01mA
100mV     -4.685mA   -2.744mA   -6.647mA
600mV     -24.29mA   -13.56mA   -35.12mA
1V        -35.2mA    -18.69mA   -51.63mA
1.4V      -40.6mA    -20.72mA   -59.71mA
2.1V      -43.28mA   -21.83mA   -63.62mA
3.7V      -45.29mA   -22.8mA    -66.51mA
3.8V      -45.39mA   -30mA      -66.64mA
4.7V      -46.01mA   -30mA      -69mA
6.6V      -46.01mA   -30mA      -69mA
[GND_clamp]
|Voltage   I(typ)   I(min)   I(max)
-3.3V     -4.767A    -5.245A    -1.798A
-1.06V    -4.767A    -5.245A    -1.798A
-990mV    -327.3mA   -5.245A    -68.38mA
-920mV    -29.22mA   -722.7mA   -11.24mA
-850mV    -6.771mA   -104.4mA   -6.721mA
-780mV    -3.56mA    -17.38mA   -4.326mA
-500mV    -59.41uA   -172uA     -34.91uA
3.28V     0A         0A         0A
[POWER_clamp]
|Voltage   I(typ)   I(min)   I(max)
-3.28V    420.5uA    175.8uA    680.7uA
-2.72V    378.4uA    175.8uA    611.5uA
-2.4V     378.3uA    175.8uA    591.3uA
-1.24V    378.3uA    175.8uA    588.9uA
-1.2V     368.9uA    175.8uA    573.6uA
-1.08V    309.6uA    172.2uA    478.3uA
-920mV    220.5uA    131.5uA    344.5uA
-760mV    139.7uA    83.77uA    224.7uA
-480mV    33.95uA    22.2uA     61.82uA
-400mV    15.86uA    14.75uA    27.74uA
-320mV    8.148uA    10.83uA    9.341uA
0V        0A         0A         0A
[Ramp]
| variable   typ   min   max
dV/dt_r  1.19492/27.07170n   0.63581/59.76837n   1.55547/13.57759n
dV/dt_f  1.27344/24.17995n   0.66960/53.20938n   1.57816/13.27864n
R_load = 50.000000
[Rising Waveform]
R_fixture= 50.000000
V_fixture= 3.300000
V_fixture_min= 2.700000
V_fixture_max= 3.600000
|time   V(typ)   V(min)   V(max)
0s        1.178V     1.575V     969.7mV
1.241ns   1.177V     1.575V     1.039V
1.542ns   1.174V     1.575V     3.086V
1.902ns   1.277V     1.575V     3.504V
2.022ns   1.567V     1.575V     3.529V
2.262ns   2.867V     1.574V     3.556V
2.583ns   3.219V     1.57V      3.576V
3.403ns   3.284V     1.686V     3.591V
4.244ns   3.293V     2.662V     3.596V
9.97ns    3.3V       2.7V       3.6V
[Rising Waveform]
R_fixture= 50.000000
V_fixture= 0.0
V_fixture_min= 0.0
V_fixture_max= 0.0
|time   V(typ)   V(min)   V(max)
0s        1.061mV    1.817mV    656.1uV
8.509ns   3.228mV    4.29mV     93.97mV
16.02ns   96.15mV    4.311mV    1.004V
25.03ns   507.2mV    7.457mV    2V
30.03ns   780.6mV    23.63mV    2.31V
37.54ns   1.157V     64.22mV    2.502V
55.56ns   1.716V     255.6mV    2.582V
77.58ns   1.93V      539.7mV    2.592V
145.1ns   1.992V     988.3mV    2.593V
249.2ns   1.993V     1.064V     2.593V
[Falling Waveform]
R_fixture= 50.000000
V_fixture= 3.300000
V_fixture_min= 2.700000
V_fixture_max= 3.600000
|time   V(typ)   V(min)   V(max)
0s        3.3V       2.7V       3.6V
12.01ns   3.3V       2.7V       3.504V
20.02ns   3.232V     2.7V       2.589V
29.53ns   2.835V     2.699V     1.502V
34.03ns   2.589V     2.693V     1.189V
39.54ns   2.276V     2.671V     1.061V
56.56ns   1.484V     2.524V     988.4mV
73.07ns   1.281V     2.303V     975.4mV
125.1ns   1.188V     1.736V     969.9mV
249.2ns   1.178V     1.575V     969.7mV
[Falling Waveform]
R_fixture= 50.000000
V_fixture= 0.0
V_fixture_min= 0.0
V_fixture_max= 0.0
|time   V(typ)   V(min)   V(max)
0s        1.993V     1.064V     2.593V
1.441ns   1.993V     1.064V     2.564V
1.542ns   1.992V     1.064V     2.321V
1.922ns   1.998V     1.064V     554.8mV
2.382ns   1.769V     1.064V     103.1mV
2.783ns   534.6mV    1.064V     49.17mV
3.303ns   75.44mV    1.069V     20.93mV
3.924ns   20.35mV    1.029V     7.943mV
5.085ns   5.225mV    55.76mV    3.539mV
9.97ns    1.061mV    1.817mV    656.1uV
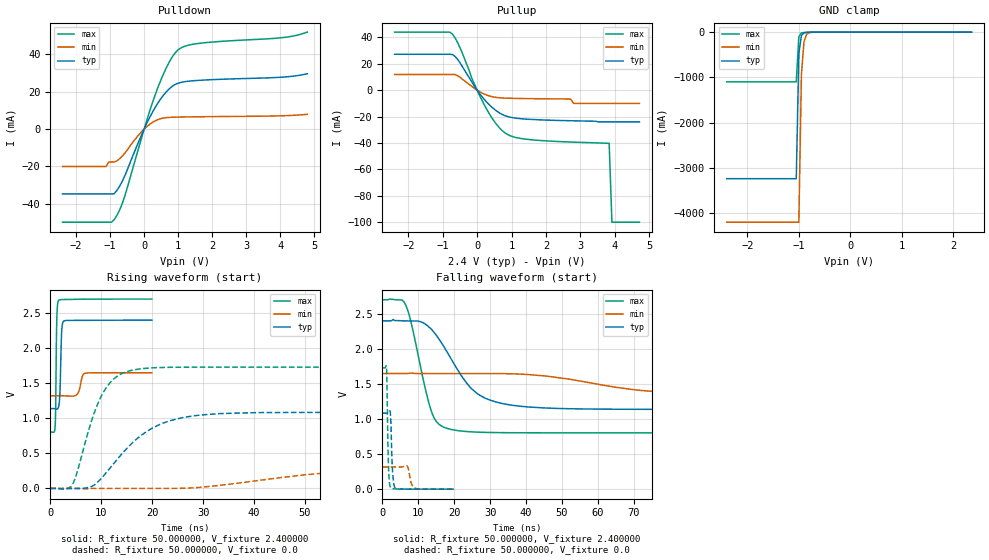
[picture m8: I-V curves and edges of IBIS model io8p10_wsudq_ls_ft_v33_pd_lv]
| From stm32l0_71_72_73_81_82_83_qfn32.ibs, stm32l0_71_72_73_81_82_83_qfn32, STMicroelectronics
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|   Model io8p10_wsudq_ls_ft_v33_pd_lv
[Model]  io8p10_wsudq_ls_ft_v33_pd_lv
Model_type I/O
Polarity   Non-Inverting
Enable   Active-Low
Vinl =   0.720000V
Vinh =   1.680000V
Vmeas =  1.200000V
Cref =   50.000000pF
Rref =   100.000000M
Vref =   0.0V
C_comp   2.582000pF   2.574200pF   2.601000pF
[Temperature Range]   25.000000   0.105000k   -40.000000
[Pullup Reference]   2.400000V   1.650000V   2.700000V
[Pulldown Reference]   0.0V   0.0V   0.0V
[POWER Clamp Reference]   2.400000V   1.650000V   2.700000V
[GND Clamp Reference]   0.0V   0.0V   0.0V
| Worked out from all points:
|   slope of the pulldown table from 0 to 0.36 V, typ, clamps not added: 28.5 ohm
|   slope of the pullup table from 0 to 0.36 V, typ, clamps not added: 32.2 ohm
|   GND clamp passes 1 mA (typ) near -0.64 V on its own axis
|   rising waveform, R_fixture 50.000000, V_fixture 2.400000: 20-80 % time 278ps typ, 630ps min, 193ps max; typ from 1.14 V to 2.4 V
|   rising waveform, R_fixture 50.000000, V_fixture 0.0: 20-80 % time 9.33ns typ, 24.7ns min, 4.81ns max; typ from 0 V to 1.08 V
|   falling waveform, R_fixture 50.000000, V_fixture 2.400000: 20-80 % time 10.1ns typ, 27ns min, 4.95ns max; typ from 2.4 V to 1.14 V
|   falling waveform, R_fixture 50.000000, V_fixture 0.0: 20-80 % time 474ps typ, 846ps min, 375ps max; typ from 1.08 V to 0 V
[Pulldown]
|Voltage   I(typ)   I(min)   I(max)
-2.4V     -34.7mA    -20mA      -49.82mA
-1.12V    -34.7mA    -20mA      -49.82mA
-1.04V    -34.7mA    -17.6mA    -49.82mA
-880mV    -34.55mA   -17.6mA    -48.46mA
-560mV    -24.65mA   -12.68mA   -35.33mA
0V        0A         0A         142fA
400mV     13.84mA    5.066mA    22.03mA
720mV     21.25mA    6.254mA    35.26mA
1.04V     24.83mA    6.464mA    43.03mA
1.6V      26.11mA    6.627mA    45.88mA
4V        27.76mA    7.125mA    48.88mA
4.8V      29.64mA    7.94mA     51.96mA
[Pullup]
|Voltage   I(typ)   I(min)   I(max)
-2.4V     27.2mA     11.88mA    44.01mA
-720mV    27.06mA    11.88mA    42.53mA
-480mV    20.06mA    9.358mA    31.11mA
-160mV    6.59mA     3.051mA    9.467mA
240mV     -7.917mA   -3.299mA   -12.65mA
560mV     -15.67mA   -5.496mA   -25.76mA
880mV     -19.92mA   -6.062mA   -33.51mA
1.68V     -22.29mA   -6.449mA   -37.81mA
2.8V      -23.2mA    -10mA      -39.35mA
3.84V     -24mA      -10mA      -40.2mA
3.92V     -24mA      -10mA      -100mA
4.72V     -24mA      -10mA      -100mA
[GND_clamp]
|Voltage   I(typ)   I(min)   I(max)
-2.4V     -3.237A    -4.198A    -1.1A
-1.05V    -3.237A    -4.198A    -1.1A
-1V       -475.9mA   -4.198A    -104.3mA
-950mV    -76.38mA   -935.5mA   -18.57mA
-900mV    -16.78mA   -213mA     -9.302mA
-850mV    -6.726mA   -51.1mA    -6.732mA
-800mV    -4.12mA    -13.96mA   -4.933mA
-650mV    -1.06mA    -1.216mA   -1.157mA
2.35V     52.69uA    50.02uA    36.84uA
[POWER_clamp]
|Voltage   I(typ)   I(min)   I(max)
-2.4V     0A         0A         0A
0V        0A         0A         0A
[Ramp]
| variable   typ   min   max
dV/dt_r  0.65004/9.31315n   0.18968/24.65064n   1.03746/4.80167n
dV/dt_f  0.75702/10.10513n   0.19716/26.96412n   1.13800/4.93601n
R_load = 50.000000
[Rising Waveform]
R_fixture= 50.000000
V_fixture= 2.400000
V_fixture_min= 1.650000
V_fixture_max= 2.700000
|time   V(typ)   V(min)   V(max)
0s        1.137V     1.32V      802.9mV
961ps     1.134V     1.32V      890.3mV
1.281ns   1.13V      1.32V      2.413V
1.642ns   1.166V     1.32V      2.679V
1.882ns   1.345V     1.32V      2.689V
2.242ns   2.244V     1.32V      2.692V
2.603ns   2.382V     1.32V      2.693V
5.285ns   2.396V     1.343V     2.696V
6.767ns   2.396V     1.639V     2.698V
19.94ns   2.399V     1.649V     2.7V
[Rising Waveform]
R_fixture= 50.000000
V_fixture= 0.0
V_fixture_min= 0.0
V_fixture_max= 0.0
|time   V(typ)   V(min)   V(max)
0s        1.421nV    7.15nV     1.172nV
4.505ns   -913.7uV   119.7uV    76.23mV
8.509ns   41.81mV    -236.2uV   1.053V
11.01ns   226.7mV    -198.4uV   1.44V
14.01ns   488.9mV    -200.6uV   1.636V
18.02ns   765.4mV    -177.3uV   1.708V
26.03ns   1.01V      2.109mV    1.728V
40.54ns   1.081V     110.1mV    1.729V
79.58ns   1.083V     302.2mV    1.729V
249.2ns   1.083V     316.1mV    1.729V
[Falling Waveform]
R_fixture= 50.000000
V_fixture= 2.400000
V_fixture_min= 1.650000
V_fixture_max= 2.700000
|time   V(typ)   V(min)   V(max)
0s        2.399V     1.649V     2.7V
6.006ns   2.399V     1.648V     2.67V
7.508ns   2.397V     1.651V     2.475V
14.01ns   2.257V     1.648V     1.061V
16.52ns   2.081V     1.648V     898.6mV
21.02ns   1.696V     1.648V     833.9mV
28.53ns   1.299V     1.648V     809.8mV
45.05ns   1.158V     1.615V     803.2mV
96.1ns    1.137V     1.343V     802.9mV
249.2ns   1.137V     1.32V      802.9mV
[Falling Waveform]
R_fixture= 50.000000
V_fixture= 0.0
V_fixture_min= 0.0
V_fixture_max= 0.0
|time   V(typ)   V(min)   V(max)
0s        1.083V     316.1mV    1.729V
1.161ns   1.083V     316.1mV    1.727V
1.522ns   1.083V     316.1mV    705.1mV
1.722ns   1.088V     316.1mV    312.1mV
2.282ns   1.044V     316.1mV    24.75mV
2.843ns   256.6mV    316.1mV    7.069mV
3.564ns   18.51mV    316.1mV    4.302mV
6.967ns   959.4uV    326.4mV    1.228mV
9.369ns   544.2uV    8.778mV    414.1uV
19.94ns   1.421nV    7.15nV     1.172nV
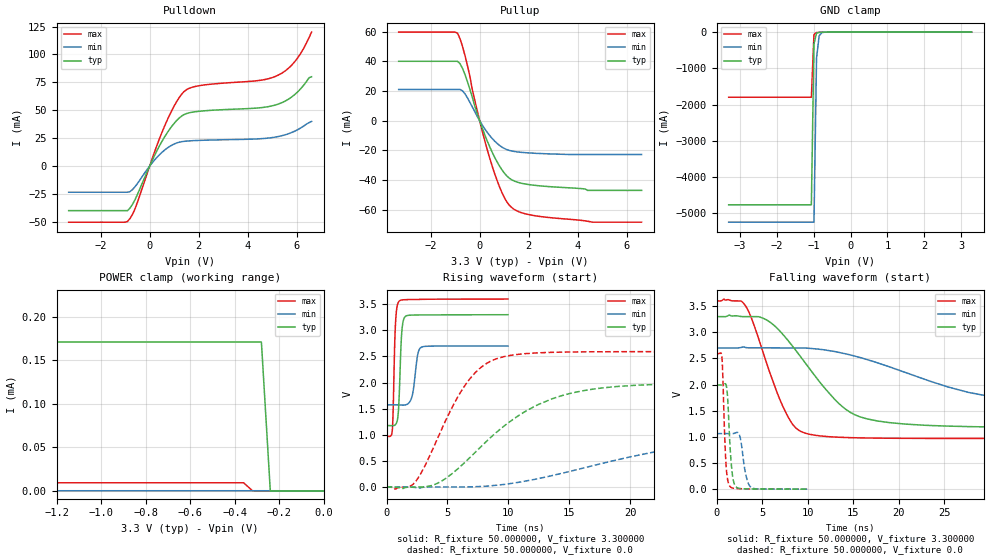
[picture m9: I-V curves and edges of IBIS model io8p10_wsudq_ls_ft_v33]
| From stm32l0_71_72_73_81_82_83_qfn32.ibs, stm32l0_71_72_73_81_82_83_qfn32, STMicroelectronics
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|   Model io8p10_wsudq_ls_ft_v33
[Model]  io8p10_wsudq_ls_ft_v33
Model_type I/O
Polarity   Non-Inverting
Enable   Active-Low
Vinl =   0.990000V
Vinh =   2.310000V
Vmeas =  1.650000V
Cref =   50.000000pF
Rref =   100.000000M
Vref =   0.0V
C_comp   2.653200pF   2.620200pF   2.695100pF
[Temperature Range]   25.000000   0.125000k   -40.000000
[Pullup Reference]   3.300000V   2.700000V   3.600000V
[Pulldown Reference]   0.0V   0.0V   0.0V
[POWER Clamp Reference]   3.300000V   2.700000V   3.600000V
[GND Clamp Reference]   0.0V   0.0V   0.0V
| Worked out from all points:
|   slope of the pulldown table from 0 to 0.495 V, typ, clamps not added: 22.6 ohm
|   slope of the pullup table from 0 to 0.495 V, typ, clamps not added: 23.9 ohm
|   GND clamp passes 1 mA (typ) near -0.64 V on its own axis
|   POWER clamp passes 1 mA (typ) near -2.99 V on its own axis
|   rising waveform, R_fixture 50.000000, V_fixture 3.300000: 20-80 % time 213ps typ, 360ps min, 178ps max; typ from 1.18 V to 3.3 V
|   rising waveform, R_fixture 50.000000, V_fixture 0.0: 20-80 % time 6.51ns typ, 13.6ns min, 3.46ns max; typ from 0 V to 1.99 V
|   falling waveform, R_fixture 50.000000, V_fixture 3.300000: 20-80 % time 5.97ns typ, 12.6ns min, 3.28ns max; typ from 3.3 V to 1.18 V
|   falling waveform, R_fixture 50.000000, V_fixture 0.0: 20-80 % time 398ps typ, 569ps min, 319ps max; typ from 1.99 V to 0 V
[Pulldown]
|Voltage   I(typ)   I(min)   I(max)
-3.3V     -39.83mA   -23.37mA   -50.2mA
-900mV    -39.83mA   -23.37mA   -49.53mA
-600mV    -30.28mA   -18.59mA   -38.45mA
500mV     22.11mA    12.28mA    30.1mA
1V        38.33mA    19.81mA    53.88mA
1.4V      46.1mA     22.18mA    66.72mA
2V        49.07mA    23.01mA    71.93mA
4.4V      52.05mA    24.38mA    76.53mA
5.2V      55.25mA    26.3mA     81.02mA
5.9V      63.83mA    31.17mA    93.18mA
6.2V      70.39mA    34.76mA    102.6mA
6.6V      80mA       40mA       120mA
[Pullup]
|Voltage   I(typ)   I(min)   I(max)
-3.3V     40.02mA    21.02mA    59.7mA
-900mV    40.02mA    21.02mA    58.93mA
-800mV    38.37mA    21.02mA    55.25mA
-600mV    31.19mA    18.18mA    44.03mA
0V        0A         25pA       0A
500mV     -20.88mA   -11.78mA   -30.07mA
900mV     -32.92mA   -17.72mA   -48.15mA
1.3V      -39.75mA   -20.4mA    -58.47mA
1.8V      -42.5mA    -21.48mA   -62.49mA
2.7V      -44.27mA   -22.29mA   -65.04mA
4.6V      -47mA      -22.8mA    -68.41mA
6.6V      -47mA      -22.8mA    -68.41mA
[GND_clamp]
|Voltage   I(typ)   I(min)   I(max)
-3.3V     -4.766A    -5.244A    -1.797A
-1.06V    -4.766A    -5.244A    -1.797A
-990mV    -326.7mA   -5.244A    -68.05mA
-920mV    -29.09mA   -722.2mA   -11.16mA
-850mV    -6.797mA   -104.4mA   -6.682mA
-780mV    -3.554mA   -17.44mA   -4.265mA
-500mV    -58.08uA   -169.3uA   -34.1uA
3.28V     0A         0A         0A
[POWER_clamp]
|Voltage   I(typ)   I(min)   I(max)
-3.28V    3.05A      15.65uA    3.723A
-3.2V     3.05A      1.687uA    3.723A
-2.96V    269.4uA    209.1nA    3.723A
-2.92V    170.9uA    209.1nA    508.5mA
-2.8V     170.9uA    209.1nA    1.296mA
-2.76V    170.9uA    209.1nA    177.1uA
-2.72V    170.9uA    209.1nA    24.25uA
-2.68V    170.9uA    209.1nA    9.362uA
-360mV    170.9uA    209.1nA    9.362uA
-280mV    170.9uA    209.1nA    0A
-240mV    0A         209.1nA    0A
0V        0A         0A         0A
[Ramp]
| variable   typ   min   max
dV/dt_r  1.19496/6.49788n   0.63054/13.57060n   1.55568/3.45906n
dV/dt_f  1.27386/5.95360n   0.65562/12.58284n   1.57856/3.27043n
R_load = 50.000000
[Rising Waveform]
R_fixture= 50.000000
V_fixture= 3.300000
V_fixture_min= 2.700000
V_fixture_max= 3.600000
|time   V(typ)   V(min)   V(max)
0s        1.177V     1.573V     969.2mV
480.5ps   1.173V     1.574V     1.104V
740.7ps   1.196V     1.574V     3.149V
1.021ns   1.642V     1.571V     3.556V
1.241ns   2.932V     1.568V     3.582V
1.542ns   3.266V     1.571V     3.588V
2.102ns   3.293V     1.74V      3.591V
2.543ns   3.295V     2.513V     3.592V
2.883ns   3.296V     2.679V     3.594V
9.97ns    3.3V       2.7V       3.6V
[Rising Waveform]
R_fixture= 50.000000
V_fixture= 0.0
V_fixture_min= 0.0
V_fixture_max= 0.0
|time   V(typ)   V(min)   V(max)
0s        -27.62uV   3.107uV    368.2uV
2.302ns   -2.007mV   -8.933mV   80.74mV
4.204ns   71.67mV    -770.2uV   936.6mV
6.507ns   486.6mV    293.9uV    1.967V
8.008ns   829.1mV    11.97mV    2.336V
9.71ns    1.177V     49.07mV    2.501V
13.61ns   1.69V      218.4mV    2.579V
18.82ns   1.922V     512.7mV    2.591V
31.43ns   1.99V      944.4mV    2.593V
49.85ns   1.992V     1.062V     2.593V
[Falling Waveform]
R_fixture= 50.000000
V_fixture= 3.300000
V_fixture_min= 2.700000
V_fixture_max= 3.600000
|time   V(typ)   V(min)   V(max)
0s        3.3V       2.7V       3.6V
3.203ns   3.3V       2.708V     3.5V
5.405ns   3.244V     2.703V     2.457V
7.407ns   2.934V     2.701V     1.534V
8.509ns   2.696V     2.7V       1.206V
9.81ns    2.396V     2.699V     1.067V
13.91ns   1.562V     2.597V     989.8mV
17.72ns   1.302V     2.412V     976.1mV
29.93ns   1.19V      1.775V     969.5mV
49.85ns   1.177V     1.573V     969.2mV
[Falling Waveform]
R_fixture= 50.000000
V_fixture= 0.0
V_fixture_min= 0.0
V_fixture_max= 0.0
|time   V(typ)   V(min)   V(max)
0s        1.992V     1.062V     2.593V
580.6ps   1.991V     1.062V     2.534V
1.021ns   2.006V     1.062V     532.2mV
1.221ns   1.733V     1.062V     179mV
1.441ns   942.1mV    1.062V     60.82mV
1.782ns   227mV      1.062V     20.48mV
2.262ns   27.36mV    1.086V     11.55mV
3.263ns   5.784mV    239.1mV    5.863mV
3.824ns   4.191mV    28.28mV    4.289mV
9.97ns    -27.62uV   3.107uV    368.2uV
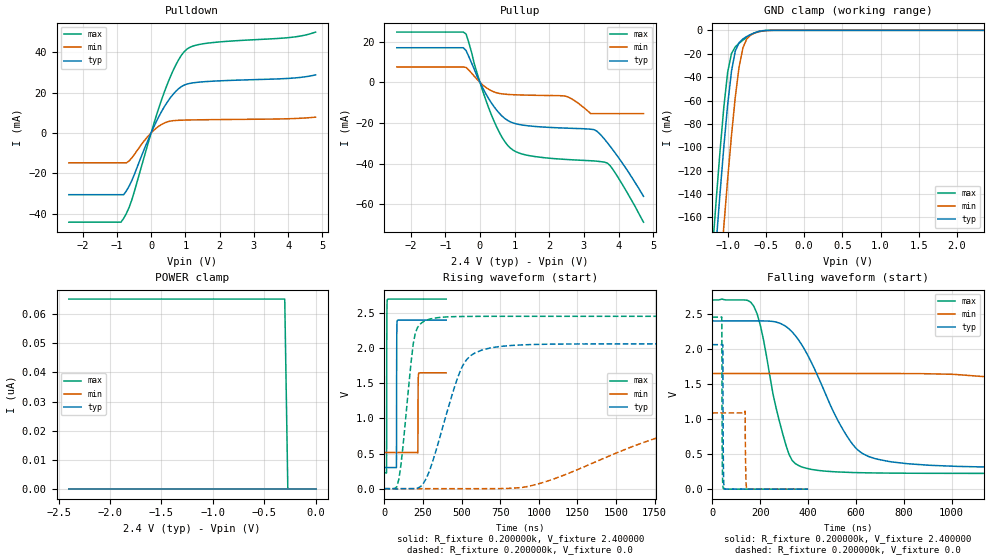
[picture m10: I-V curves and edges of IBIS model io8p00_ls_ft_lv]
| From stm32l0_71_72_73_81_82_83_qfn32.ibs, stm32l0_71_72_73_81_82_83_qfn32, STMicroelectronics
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|   Model io8p00_ls_ft_lv
[Model]  io8p00_ls_ft_lv
Model_type I/O
Polarity   Non-Inverting
Enable   Active-Low
Vinl =   0.720000V
Vinh =   1.680000V
Vmeas =  1.200000V
Cref =   50.000000pF
Rref =   100.000000M
Vref =   0.0V
C_comp   4.521100pF   4.438000pF   4.578000pF
[Temperature Range]   25.000000   0.105000k   -40.000000
[Pullup Reference]   2.400000V   1.650000V   2.700000V
[Pulldown Reference]   0.0V   0.0V   0.0V
[POWER Clamp Reference]   2.400000V   1.650000V   2.700000V
[GND Clamp Reference]   0.0V   0.0V   0.0V
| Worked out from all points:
|   slope of the pulldown table from 0 to 0.36 V, typ, clamps not added: 29.5 ohm
|   slope of the pullup table from 0 to 0.36 V, typ, clamps not added: 33.2 ohm
|   GND clamp passes 1 mA (typ) near -0.59 V on its own axis
|   rising waveform, R_fixture 0.200000k, V_fixture 2.400000: 20-80 % time 1.16ns typ, 1.17ns min, 1.15ns max; typ from 0.301 V to 2.4 V
|   rising waveform, R_fixture 0.200000k, V_fixture 0.0: 20-80 % time 171ns typ, 823ns min, 66.9ns max; typ from 0 V to 2.06 V
|   falling waveform, R_fixture 0.200000k, V_fixture 2.400000: 20-80 % time 182ns typ, 736ns min, 90.8ns max; typ from 2.4 V to 0.301 V
|   falling waveform, R_fixture 0.200000k, V_fixture 0.0: 20-80 % time 1.74ns typ, 2.35ns min, 1.52ns max; typ from 2.06 V to 0 V
[Pulldown]
|Voltage   I(typ)   I(min)   I(max)
-2.4V     -30.64mA   -14.84mA   -44.29mA
-880mV    -30.64mA   -14.84mA   -44.29mA
-800mV    -30.64mA   -14.84mA   -42.37mA
-560mV    -23.52mA   -12.34mA   -33.09mA
0V        -765.2nA   -61.09nA   -2.527uA
400mV     13.38mA    4.998mA    20.91mA
720mV     20.62mA    6.178mA    33.69mA
880mV     22.92mA    6.307mA    38.42mA
1.04V     24.19mA    6.384mA    41.49mA
1.6V      25.46mA    6.544mA    44.42mA
4V        27.04mA    7.029mA    47.25mA
4.8V      28.77mA    7.818mA    50.02mA
[Pullup]
|Voltage   I(typ)   I(min)   I(max)
-2.4V     17.07mA    7.61mA     24.78mA
-400mV    15.68mA    7.363mA    23.82mA
-80mV     2.912mA    1.471mA    4.444mA
240mV     -7.653mA   -3.251mA   -12mA
560mV     -15.22mA   -5.43mA    -24.63mA
800mV     -18.73mA   -5.908mA   -31mA
1.28V     -21.13mA   -6.236mA   -35.54mA
2.48V     -22.51mA   -6.819mA   -37.93mA
3.2V      -23.05mA   -15.37mA   -38.57mA
3.36V     -23.83mA   -15.37mA   -38.77mA
3.76V     -31.5mA    -15.37mA   -41.06mA
4.72V     -56.1mA    -15.37mA   -68.83mA
[GND_clamp]
|Voltage   I(typ)   I(min)   I(max)
-2.4V     -1.379A    -1.445A    -1.35A
-1.2V     -225.9mA   -297.5mA   -189.2mA
-1.15V    -182mA     -253.1mA   -145.3mA
-1.1V     -139.6mA   -209.7mA   -103.5mA
-1.05V    -99.61mA   -167.6mA   -65.7mA
-1V       -63.67mA   -127.3mA   -35.89mA
-950mV    -35mA      -89.93mA   -19.87mA
-900mV    -17.67mA   -57.01mA   -14.12mA
-850mV    -10.49mA   -31.18mA   -11mA
-750mV    -5.288mA   -7.322mA   -5.997mA
-450mV    -33.57uA   -87.56uA   -14.35uA
2.35V     0A         0A         0A
[POWER_clamp]
|Voltage   I(typ)   I(min)   I(max)
-2.4V     0A         0A         65.17nA
-300mV    0A         0A         65.17nA
-270mV    0A         0A         0A
0V        0A         0A         0A
[Ramp]
| variable   typ   min   max
dV/dt_r  0.63779/0.30050u   0.18779/0.81004u   1.01572/0.14383u
dV/dt_f  0.74034/0.32404u   0.19434/0.85424u   1.11789/0.16281u
R_load = 50.000000
[Rising Waveform]
R_fixture= 0.200000k
V_fixture= 2.400000
V_fixture_min= 1.650000
V_fixture_max= 2.700000
|time   V(typ)   V(min)   V(max)
0s        301mV      514.7mV    224.8mV
13.61ns   301mV      514.7mV    224mV
15.62ns   301mV      514.7mV    2.368V
19.22ns   301mV      514.7mV    2.694V
77.68ns   304.7mV    514.7mV    2.7V
79.68ns   2.089V     514.7mV    2.7V
82.88ns   2.392V     514.7mV    2.7V
215.8ns   2.4V       510.2mV    2.7V
222.2ns   2.4V       1.645V     2.7V
400ns     2.4V       1.65V      2.7V
[Rising Waveform]
R_fixture= 0.200000k
V_fixture= 0.0
V_fixture_min= 0.0
V_fixture_max= 0.0
|time   V(typ)   V(min)   V(max)
0s        17.38uV    2.738uV    39.86uV
93.43ns   -108.9uV   2.738uV    134.8mV
200.2ns   1.707mV    2.738uV    2.217V
280.3ns   191.5mV    -23.4uV    2.405V
373.7ns   846.6mV    -23.54uV   2.441V
533.9ns   1.84V      6.186uV    2.452V
894.2ns   2.048V     18.79mV    2.454V
1.909us   2.062V     814.9mV    2.454V
2.789us   2.062V     1.052V     2.454V
13.33us   2.062V     1.088V     2.454V
[Falling Waveform]
R_fixture= 0.200000k
V_fixture= 2.400000
V_fixture_min= 1.650000
V_fixture_max= 2.700000
|time   V(typ)   V(min)   V(max)
0s        2.4V       1.65V      2.7V
173.5ns   2.4V       1.65V      2.608V
320.3ns   2.287V     1.65V      496.8mV
520.5ns   1.005V     1.65V      246.2mV
627.3ns   508.4mV    1.65V      234.4mV
814.1ns   363.3mV    1.649V     227.5mV
1.361us   307.6mV    1.497V     224.9mV
2.216us   301.3mV    730.1mV    224.8mV
3.03us    301mV      556.1mV    224.8mV
13.33us   301mV      514.7mV    224.8mV
[Falling Waveform]
R_fixture= 0.200000k
V_fixture= 0.0
V_fixture_min= 0.0
V_fixture_max= 0.0
|time   V(typ)   V(min)   V(max)
0s        2.062V     1.088V     2.454V
39.24ns   2.062V     1.088V     2.456V
41.64ns   2.062V     1.088V     371.9mV
43.64ns   2.064V     1.088V     62.42mV
45.25ns   708.8mV    1.088V     16.78mV
46.45ns   250.9mV    1.088V     6.856mV
136.5ns   50.19uV    1.113V     139.5uV
140.1ns   49.11uV    156.8mV    139.1uV
145.3ns   47.56uV    3.186mV    138.5uV
400ns     17.38uV    2.738uV    39.86uV
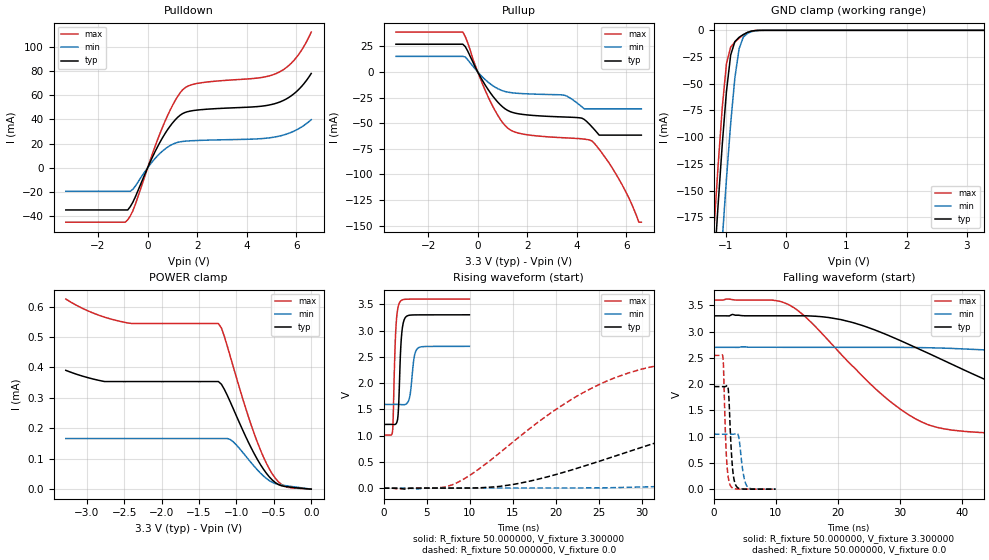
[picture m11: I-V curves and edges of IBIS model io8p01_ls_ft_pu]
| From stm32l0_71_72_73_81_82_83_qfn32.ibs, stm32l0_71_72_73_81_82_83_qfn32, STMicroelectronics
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|   Model io8p01_ls_ft_pu
[Model]  io8p01_ls_ft_pu
Model_type I/O
Polarity   Non-Inverting
Enable   Active-Low
Vinl =   0.990000V
Vinh =   2.310000V
Vmeas =  1.650000V
Cref =   50.000000pF
Rref =   100.000000M
Vref =   0.0V
C_comp   4.606100pF   4.563500pF   4.706200pF
[Temperature Range]   25.000000   0.125000k   -40.000000
[Pullup Reference]   3.300000V   2.700000V   3.600000V
[Pulldown Reference]   0.0V   0.0V   0.0V
[POWER Clamp Reference]   3.300000V   2.700000V   3.600000V
[GND Clamp Reference]   0.0V   0.0V   0.0V
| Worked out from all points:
|   slope of the pulldown table from 0 to 0.495 V, typ, clamps not added: 23.6 ohm
|   slope of the pullup table from 0 to 0.495 V, typ, clamps not added: 24.9 ohm
|   GND clamp passes 1 mA (typ) near -0.59 V on its own axis
|   rising waveform, R_fixture 50.000000, V_fixture 3.300000: 20-80 % time 315ps typ, 426ps min, 298ps max; typ from 1.22 V to 3.3 V
|   rising waveform, R_fixture 50.000000, V_fixture 0.0: 20-80 % time 27.1ns typ, 59.7ns min, 13.7ns max; typ from 0.001 V to 1.95 V
|   falling waveform, R_fixture 50.000000, V_fixture 3.300000: 20-80 % time 24.7ns typ, 53.4ns min, 13.5ns max; typ from 3.3 V to 1.22 V
|   falling waveform, R_fixture 50.000000, V_fixture 0.0: 20-80 % time 526ps typ, 689ps min, 462ps max; typ from 1.95 V to 0.001 V
[Pulldown]
|Voltage   I(typ)   I(min)   I(max)
-3.3V     -34.78mA   -19.34mA   -44.89mA
-900mV    -34.78mA   -19.34mA   -44.89mA
-800mV    -34.78mA   -19.34mA   -42.84mA
-600mV    -28.56mA   -17.8mA    -35.75mA
100mV     4.638mA    2.744mA    6.076mA
600mV     24.8mA     13.84mA    33.52mA
1V        36.93mA    19.4mA     51.35mA
1.4V      44.67mA    21.76mA    64.17mA
2V        47.71mA    22.58mA    69.7mA
5.2V      53.42mA    25.71mA    78.01mA
6V        62.87mA    31.27mA    91.1mA
6.6V      77.92mA    39.75mA    112.1mA
[Pullup]
|Voltage   I(typ)   I(min)   I(max)
-3.3V     27.07mA    15.24mA    38.94mA
-600mV    27.07mA    15.24mA    38.94mA
400mV     -16.48mA   -9.566mA   -23.24mA
1.1V      -35.89mA   -19.06mA   -52.21mA
1.7V      -41.02mA   -20.95mA   -60.01mA
3.5V      -43.94mA   -22.7mA    -64.24mA
4.2V      -45.07mA   -33.96mA   -65.24mA
4.6V      -53.38mA   -35.99mA   -67.22mA
4.9V      -61.63mA   -35.99mA   -75.49mA
5.8V      -61.63mA   -35.99mA   -109mA
6.5V      -61.63mA   -35.99mA   -146.6mA
6.6V      -61.63mA   -35.99mA   -146.6mA
[GND_clamp]
|Voltage   I(typ)   I(min)   I(max)
-3.3V     -2.276A    -2.356A    -2.25A
-1.2V     -226mA     -318.7mA   -189.2mA
-1.13V    -164.9mA   -256.6mA   -128.3mA
-1.06V    -107.5mA   -196.5mA   -72.78mA
-990mV    -57.32mA   -139.4mA   -31.39mA
-920mV    -23.22mA   -87.32mA   -15.73mA
-850mV    -10.58mA   -44.45mA   -10.94mA
-780mV    -6.539mA   -17.25mA   -7.356mA
-710mV    -3.933mA   -6.349mA   -4.308mA
-640mV    -1.955mA   -2.79mA    -1.975mA
-360mV    -2.06uA    -16.21uA   -459.5nA
3.28V     0A         0A         0A
[POWER_clamp]
|Voltage   I(typ)   I(min)   I(max)
-3.28V    390.5uA    166.4uA    624.7uA
-2.76V    353.6uA    166.4uA    565.1uA
-2.44V    353.6uA    166.4uA    545.7uA
-1.24V    353.6uA    166.4uA    544.1uA
-1.2V     344.6uA    166.4uA    529.4uA
-1.16V    327.5uA    166.4uA    501.1uA
-1.04V    263.2uA    155.2uA    400.5uA
-760mV    115.6uA    74.53uA    180.9uA
-560mV    40.33uA    28.04uA    66.46uA
-440mV    15.38uA    15.6uA     24.56uA
-360mV    9.136uA    12.12uA    10.1uA
0V        0A         0A         0A
[Ramp]
| variable   typ   min   max
dV/dt_r  1.17099/27.11398n   0.62522/59.35477n   1.52743/13.66460n
dV/dt_f  1.25094/24.63010n   0.65754/53.28112n   1.55250/13.52037n
R_load = 50.000000
[Rising Waveform]
R_fixture= 50.000000
V_fixture= 3.300000
V_fixture_min= 2.700000
V_fixture_max= 3.600000
|time   V(typ)   V(min)   V(max)
0s        1.215V     1.595V     1.012V
1.021ns   1.214V     1.595V     1.068V
1.421ns   1.224V     1.595V     3.038V
1.682ns   1.407V     1.595V     3.449V
1.882ns   2.235V     1.593V     3.541V
2.162ns   3.032V     1.59V      3.582V
2.623ns   3.266V     1.604V     3.596V
3.043ns   3.292V     1.749V     3.598V
3.924ns   3.298V     2.657V     3.599V
9.97ns    3.3V       2.7V       3.599V
[Rising Waveform]
R_fixture= 50.000000
V_fixture= 0.0
V_fixture_min= 0.0
V_fixture_max= 0.0
|time   V(typ)   V(min)   V(max)
0s        1.146mV    1.863mV    784.1uV
8.008ns   3.241mV    4.295mV    66.73mV
15.02ns   71.15mV    4.303mV    877.4mV
24.52ns   484.5mV    7.34mV     1.932V
30.53ns   806.4mV    26.46mV    2.288V
38.04ns   1.167V     69.65mV    2.461V
55.06ns   1.676V     250mV      2.535V
77.08ns   1.89V      529.7mV    2.546V
135.1ns   1.951V     944.7mV    2.546V
249.2ns   1.953V     1.046V     2.546V
[Falling Waveform]
R_fixture= 50.000000
V_fixture= 3.300000
V_fixture_min= 2.700000
V_fixture_max= 3.600000
|time   V(typ)   V(min)   V(max)
0s        3.3V       2.7V       3.599V
12.01ns   3.3V       2.7V       3.518V
20.52ns   3.227V     2.7V       2.57V
30.03ns   2.832V     2.699V     1.53V
35.04ns   2.564V     2.691V     1.209V
40.54ns   2.261V     2.668V     1.099V
57.06ns   1.523V     2.527V     1.032V
73.07ns   1.322V     2.317V     1.018V
129.6ns   1.224V     1.737V     1.012V
249.2ns   1.215V     1.595V     1.012V
[Falling Waveform]
R_fixture= 50.000000
V_fixture= 0.0
V_fixture_min= 0.0
V_fixture_max= 0.0
|time   V(typ)   V(min)   V(max)
0s        1.953V     1.046V     2.546V
1.481ns   1.953V     1.046V     2.508V
2.042ns   1.965V     1.046V     621.3mV
2.362ns   1.87V      1.046V     206.1mV
2.643ns   1.172V     1.046V     79.17mV
3.063ns   359.6mV    1.046V     19.84mV
3.644ns   56.06mV    1.066V     4.328mV
4.044ns   16.58mV    981.2mV    2.712mV
5.285ns   1.863mV    72.02mV    1.58mV
9.97ns    1.146mV    1.863mV    784.1uV
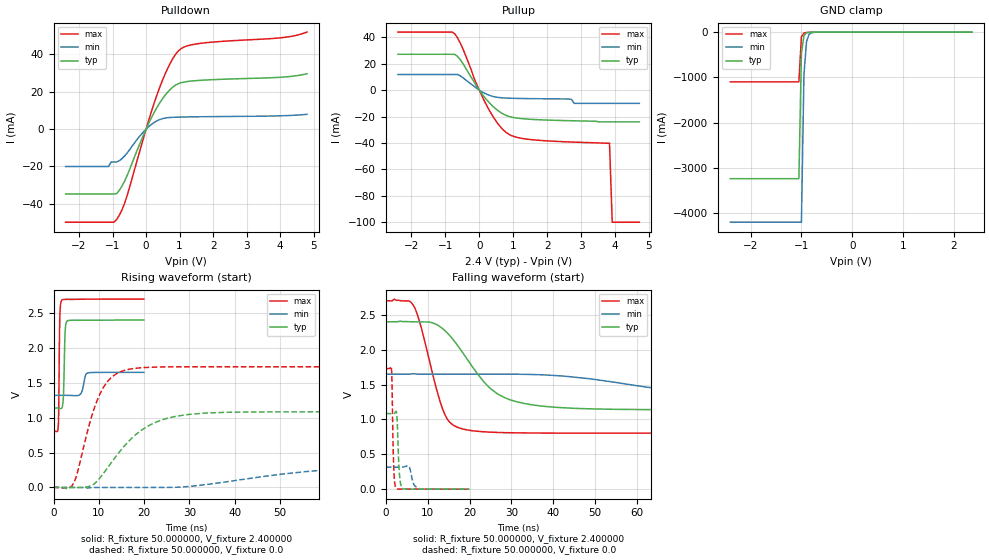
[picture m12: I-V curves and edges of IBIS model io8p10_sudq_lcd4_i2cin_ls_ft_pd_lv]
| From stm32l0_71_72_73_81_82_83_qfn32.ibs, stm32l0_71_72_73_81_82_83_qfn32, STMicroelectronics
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|   Model io8p10_sudq_lcd4_i2cin_ls_ft_pd_lv
[Model]  io8p10_sudq_lcd4_i2cin_ls_ft_pd_lv
Model_type I/O
Polarity   Non-Inverting
Enable   Active-Low
Vinl =   0.720000V
Vinh =   1.680000V
Vmeas =  1.200000V
Cref =   50.000000pF
Rref =   100.000000M
Vref =   0.0V
C_comp   2.470900pF   2.435200pF   2.490500pF
[Temperature Range]   25.000000   0.105000k   -40.000000
[Pullup Reference]   2.400000V   1.650000V   2.700000V
[Pulldown Reference]   0.0V   0.0V   0.0V
[POWER Clamp Reference]   2.400000V   1.650000V   2.700000V
[GND Clamp Reference]   0.0V   0.0V   0.0V
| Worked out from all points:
|   slope of the pulldown table from 0 to 0.36 V, typ, clamps not added: 28.5 ohm
|   slope of the pullup table from 0 to 0.36 V, typ, clamps not added: 32.2 ohm
|   GND clamp passes 1 mA (typ) near -0.64 V on its own axis
|   rising waveform, R_fixture 50.000000, V_fixture 2.400000: 20-80 % time 282ps typ, 634ps min, 193ps max; typ from 1.14 V to 2.4 V
|   rising waveform, R_fixture 50.000000, V_fixture 0.0: 20-80 % time 9.34ns typ, 24.7ns min, 4.81ns max; typ from 0 V to 1.08 V
|   falling waveform, R_fixture 50.000000, V_fixture 2.400000: 20-80 % time 10.1ns typ, 26.8ns min, 4.94ns max; typ from 2.4 V to 1.14 V
|   falling waveform, R_fixture 50.000000, V_fixture 0.0: 20-80 % time 456ps typ, 828ps min, 358ps max; typ from 1.08 V to 0 V
[Pulldown]
|Voltage   I(typ)   I(min)   I(max)
-2.4V     -34.7mA    -20mA      -49.82mA
-1.12V    -34.7mA    -20mA      -49.82mA
-1.04V    -34.7mA    -17.6mA    -49.82mA
-880mV    -34.55mA   -17.6mA    -48.46mA
-560mV    -24.65mA   -12.68mA   -35.33mA
0V        326fA      0A         16fA
400mV     13.84mA    5.066mA    22.03mA
720mV     21.25mA    6.254mA    35.26mA
1.04V     24.83mA    6.464mA    43.03mA
1.6V      26.11mA    6.627mA    45.88mA
4V        27.76mA    7.125mA    48.88mA
4.8V      29.64mA    7.94mA     51.96mA
[Pullup]
|Voltage   I(typ)   I(min)   I(max)
-2.4V     27.2mA     11.88mA    44.01mA
-720mV    27.06mA    11.88mA    42.53mA
-480mV    20.06mA    9.358mA    31.11mA
-160mV    6.59mA     3.051mA    9.467mA
240mV     -7.917mA   -3.299mA   -12.65mA
560mV     -15.67mA   -5.496mA   -25.76mA
880mV     -19.92mA   -6.062mA   -33.51mA
1.68V     -22.29mA   -6.449mA   -37.81mA
2.8V      -23.2mA    -10mA      -39.35mA
3.84V     -24mA      -10mA      -40.2mA
3.92V     -24mA      -10mA      -100mA
4.72V     -24mA      -10mA      -100mA
[GND_clamp]
|Voltage   I(typ)   I(min)   I(max)
-2.4V     -3.237A    -4.197A    -1.1A
-1.05V    -3.237A    -4.197A    -1.1A
-1V       -475.5mA   -4.197A    -104.1mA
-950mV    -76.09mA   -935.1mA   -18.45mA
-900mV    -16.59mA   -212.6mA   -9.272mA
-850mV    -6.633mA   -50.89mA   -6.773mA
-800mV    -4.105mA   -13.86mA   -5.003mA
-650mV    -1.082mA   -1.227mA   -1.183mA
2.35V     52.69uA    50.02uA    36.84uA
[POWER_clamp]
|Voltage   I(typ)   I(min)   I(max)
-2.4V     0A         0A         0A
0V        0A         0A         0A
[Ramp]
| variable   typ   min   max
dV/dt_r  0.65004/9.32786n   0.18968/24.67363n   1.03746/4.80056n
dV/dt_f  0.75702/10.07793n   0.19716/26.73625n   1.13800/4.92217n
R_load = 50.000000
[Rising Waveform]
R_fixture= 50.000000
V_fixture= 2.400000
V_fixture_min= 1.650000
V_fixture_max= 2.700000
|time   V(typ)   V(min)   V(max)
0s        1.137V     1.32V      802.9mV
1.041ns   1.137V     1.32V      870.1mV
1.161ns   1.136V     1.32V      1.193V
1.361ns   1.133V     1.32V      2.355V
1.762ns   1.134V     1.32V      2.677V
2.202ns   1.342V     1.32V      2.693V
2.603ns   2.274V     1.32V      2.695V
3.003ns   2.383V     1.32V      2.695V
7.487ns   2.396V     1.639V     2.698V
19.94ns   2.399V     1.649V     2.7V
[Rising Waveform]
R_fixture= 50.000000
V_fixture= 0.0
V_fixture_min= 0.0
V_fixture_max= 0.0
|time   V(typ)   V(min)   V(max)
0s        -771.4nV   -3.33uV    -399.6nV
4.505ns   -895.7uV   98.15uV    66.77mV
8.509ns   33.28mV    -930uV     1.038V
11.51ns   244.8mV    -196.5uV   1.481V
14.01ns   464.8mV    -199.5uV   1.633V
18.02ns   748.8mV    -182.8uV   1.707V
26.53ns   1.013V     1.682mV    1.728V
39.04ns   1.078V     89.02mV    1.729V
81.08ns   1.083V     303.1mV    1.729V
249.2ns   1.083V     316.1mV    1.729V
[Falling Waveform]
R_fixture= 50.000000
V_fixture= 2.400000
V_fixture_min= 1.650000
V_fixture_max= 2.700000
|time   V(typ)   V(min)   V(max)
0s        2.399V     1.649V     2.7V
6.507ns   2.399V     1.655V     2.643V
8.008ns   2.397V     1.649V     2.409V
14.01ns   2.277V     1.648V     1.081V
16.02ns   2.147V     1.648V     921.1mV
21.02ns   1.725V     1.648V     834.9mV
29.03ns   1.295V     1.648V     809.4mV
45.55ns   1.157V     1.602V     803.2mV
92.09ns   1.137V     1.346V     802.9mV
249.2ns   1.137V     1.32V      802.9mV
[Falling Waveform]
R_fixture= 50.000000
V_fixture= 0.0
V_fixture_min= 0.0
V_fixture_max= 0.0
|time   V(typ)   V(min)   V(max)
0s        1.083V     316.1mV    1.729V
1.321ns   1.083V     316.1mV    1.743V
1.441ns   1.083V     316.1mV    1.581V
1.882ns   1.083V     316.1mV    322.4mV
2.442ns   1.116V     316.1mV    18.06mV
2.683ns   1.011V     316.1mV    6.09mV
3.203ns   247.1mV    315.9mV    1.561mV
3.884ns   15.06mV    315.7mV    1.251mV
7.928ns   400.7uV    7.533mV    829.1uV
19.94ns   -771.4nV   -3.33uV    -399.6nV
